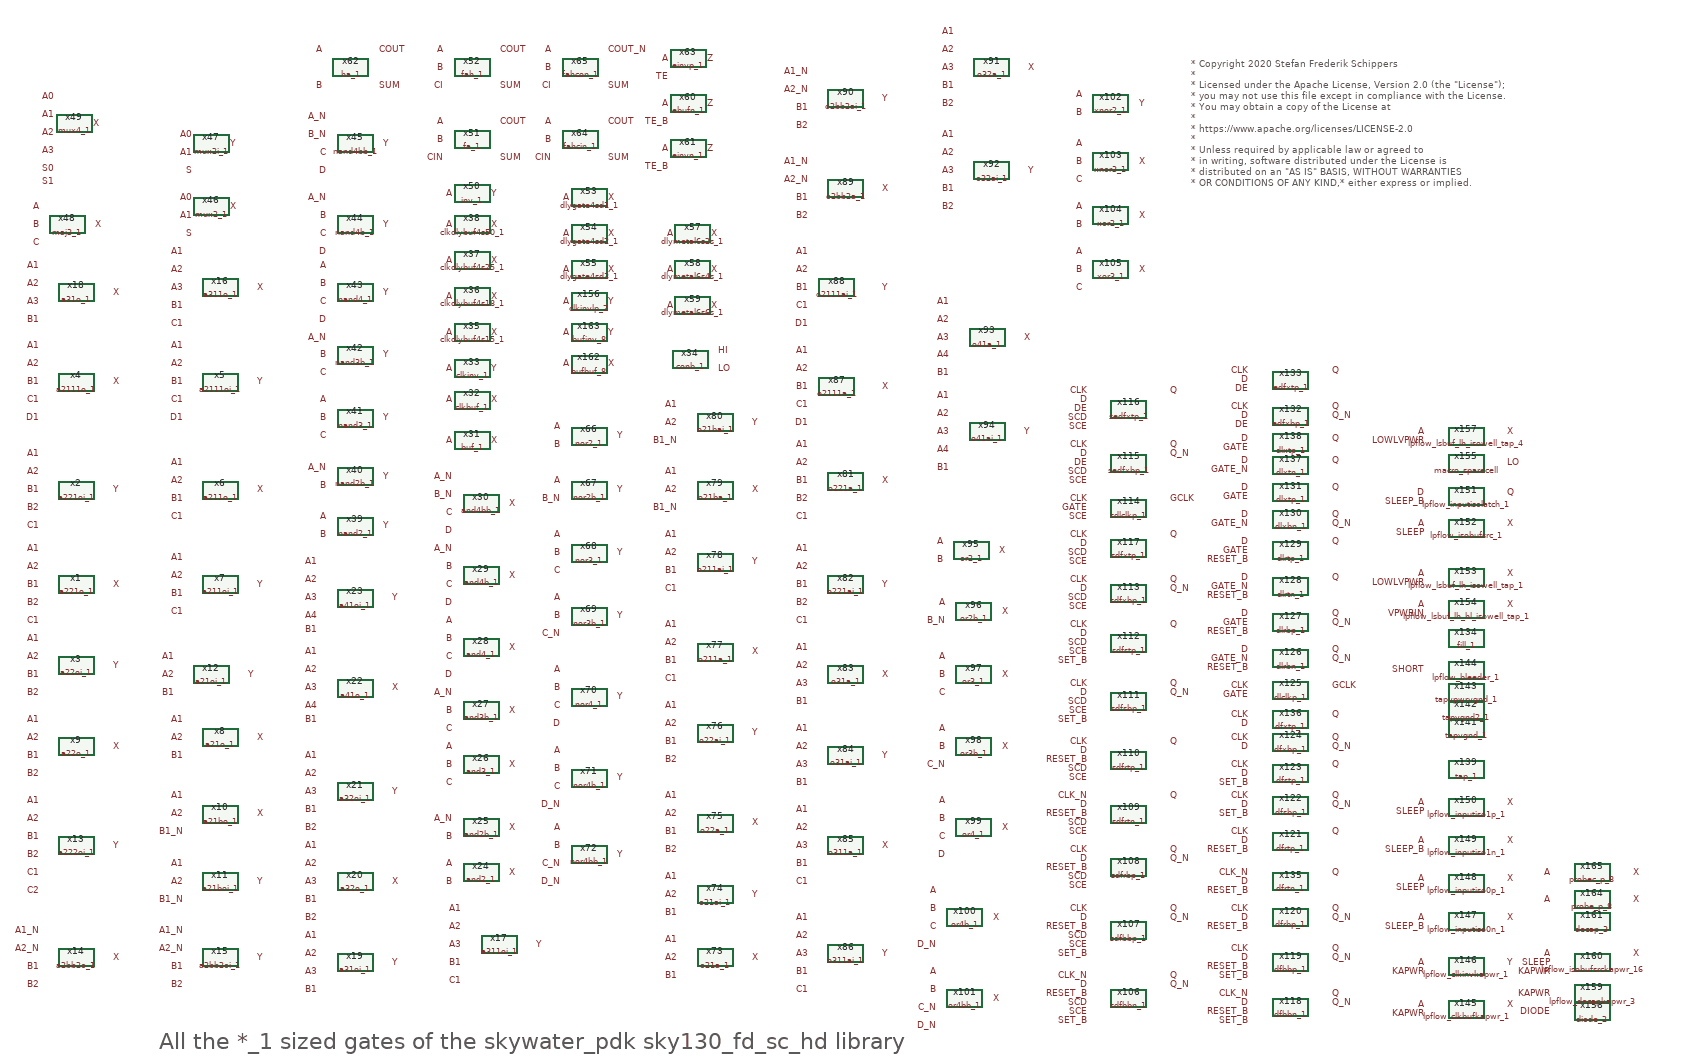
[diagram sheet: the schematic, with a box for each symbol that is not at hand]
v {xschem version=2.9.9 file_version=1.2 }
G {}
K {}
V {}
S {}
E {}
T {All the *_1 sized gates of the skywater_pdk sky130_fd_sc_hd library} 345 -215 0 0 2 2 {layer=1}
T {* Copyright 2020 Stefan Frederik Schippers
* 
* Licensed under the Apache License, Version 2.0 (the "License");
* you may not use this file except in compliance with the License.
* You may obtain a copy of the License at
*
*     https://www.apache.org/licenses/LICENSE-2.0
*
* Unless required by applicable law or agreed to
* in writing, software distributed under the License is
* distributed on an "AS IS" BASIS, WITHOUT WARRANTIES
* OR CONDITIONS OF ANY KIND,* either express or implied.
* See the License for the specific language governing
* permissions and limitations under the License.
} 2640 -2390 0 0 0.6 0.6 {}
C {sky130_stdcells/a221o_1.sym} 160 -1220 0 0 {name=x1 VGND=VGND VNB=VNB VPB=VPB VPWR=VPWR prefix=sky130_fd_sc_hd__ }
C {devices/lab_pin.sym} 80 -1300 0 0 {name=p1 lab=A1}
C {devices/lab_pin.sym} 80 -1260 0 0 {name=p2 lab=A2}
C {devices/lab_pin.sym} 80 -1220 0 0 {name=p3 lab=B1}
C {devices/lab_pin.sym} 80 -1180 0 0 {name=p4 lab=B2}
C {devices/lab_pin.sym} 80 -1140 0 0 {name=p5 lab=C1}
C {devices/lab_pin.sym} 240 -1220 0 1 {name=p6 lab=X}
C {sky130_stdcells/a221oi_1.sym} 160 -1430 0 0 {name=x2 VGND=VGND VNB=VNB VPB=VPB VPWR=VPWR prefix=sky130_fd_sc_hd__ }
C {devices/lab_pin.sym} 80 -1510 0 0 {name=p7 lab=A1}
C {devices/lab_pin.sym} 80 -1470 0 0 {name=p8 lab=A2}
C {devices/lab_pin.sym} 80 -1430 0 0 {name=p9 lab=B1}
C {devices/lab_pin.sym} 80 -1390 0 0 {name=p10 lab=B2}
C {devices/lab_pin.sym} 80 -1350 0 0 {name=p11 lab=C1}
C {sky130_stdcells/a22oi_1.sym} 160 -1040 0 0 {name=x3 VGND=VGND VNB=VNB VPB=VPB VPWR=VPWR prefix=sky130_fd_sc_hd__ }
C {devices/lab_pin.sym} 80 -1100 0 0 {name=p13 lab=A1}
C {devices/lab_pin.sym} 80 -1060 0 0 {name=p14 lab=A2}
C {devices/lab_pin.sym} 80 -1020 0 0 {name=p15 lab=B1}
C {devices/lab_pin.sym} 80 -980 0 0 {name=p16 lab=B2}
C {devices/lab_pin.sym} 240 -1040 0 1 {name=p17 lab=Y}
C {devices/title.sym} 160 -30 0 0 {name=l1 author="Stefan Schippers"}
C {sky130_stdcells/a2111o_1.sym} 160 -1670 0 0 {name=x4 VGND=VGND VNB=VNB VPB=VPB VPWR=VPWR prefix=sky130_fd_sc_hd__ }
C {devices/lab_pin.sym} 80 -1750 0 0 {name=p18 lab=A1}
C {devices/lab_pin.sym} 80 -1710 0 0 {name=p19 lab=A2}
C {devices/lab_pin.sym} 80 -1670 0 0 {name=p20 lab=B1}
C {devices/lab_pin.sym} 80 -1630 0 0 {name=p21 lab=C1}
C {devices/lab_pin.sym} 80 -1590 0 0 {name=p22 lab=D1}
C {devices/lab_pin.sym} 240 -1670 0 1 {name=p23 lab=X}
C {sky130_stdcells/a2111oi_1.sym} 480 -1670 0 0 {name=x5 VGND=VGND VNB=VNB VPB=VPB VPWR=VPWR prefix=sky130_fd_sc_hd__ }
C {devices/lab_pin.sym} 400 -1750 0 0 {name=p24 lab=A1}
C {devices/lab_pin.sym} 400 -1710 0 0 {name=p25 lab=A2}
C {devices/lab_pin.sym} 400 -1670 0 0 {name=p26 lab=B1}
C {devices/lab_pin.sym} 400 -1630 0 0 {name=p27 lab=C1}
C {devices/lab_pin.sym} 400 -1590 0 0 {name=p28 lab=D1}
C {sky130_stdcells/a211o_1.sym} 480 -1430 0 0 {name=x6 VGND=VGND VNB=VNB VPB=VPB VPWR=VPWR prefix=sky130_fd_sc_hd__ }
C {devices/lab_pin.sym} 400 -1490 0 0 {name=p30 lab=A1}
C {devices/lab_pin.sym} 400 -1450 0 0 {name=p31 lab=A2}
C {devices/lab_pin.sym} 400 -1410 0 0 {name=p32 lab=B1}
C {devices/lab_pin.sym} 400 -1370 0 0 {name=p33 lab=C1}
C {devices/lab_pin.sym} 560 -1430 0 1 {name=p34 lab=X}
C {sky130_stdcells/a211oi_1.sym} 480 -1220 0 0 {name=x7 VGND=VGND VNB=VNB VPB=VPB VPWR=VPWR prefix=sky130_fd_sc_hd__ }
C {devices/lab_pin.sym} 400 -1280 0 0 {name=p35 lab=A1}
C {devices/lab_pin.sym} 400 -1240 0 0 {name=p36 lab=A2}
C {devices/lab_pin.sym} 400 -1200 0 0 {name=p37 lab=B1}
C {devices/lab_pin.sym} 400 -1160 0 0 {name=p38 lab=C1}
C {devices/lab_pin.sym} 560 -1220 0 1 {name=p39 lab=Y}
C {devices/lab_pin.sym} 560 -1670 0 1 {name=p29 lab=Y}
C {devices/lab_pin.sym} 240 -1430 0 1 {name=p12 lab=Y}
C {sky130_stdcells/a21o_1.sym} 480 -880 0 0 {name=x8 VGND=VGND VNB=VNB VPB=VPB VPWR=VPWR prefix=sky130_fd_sc_hd__ }
C {devices/lab_pin.sym} 400 -920 0 0 {name=p40 lab=A1}
C {devices/lab_pin.sym} 400 -880 0 0 {name=p41 lab=A2}
C {devices/lab_pin.sym} 400 -840 0 0 {name=p42 lab=B1}
C {devices/lab_pin.sym} 560 -880 0 1 {name=p43 lab=X}
C {sky130_stdcells/a22o_1.sym} 160 -860 0 0 {name=x9 VGND=VGND VNB=VNB VPB=VPB VPWR=VPWR prefix=sky130_fd_sc_hd__ }
C {devices/lab_pin.sym} 80 -920 0 0 {name=p44 lab=A1}
C {devices/lab_pin.sym} 80 -880 0 0 {name=p45 lab=A2}
C {devices/lab_pin.sym} 80 -840 0 0 {name=p46 lab=B1}
C {devices/lab_pin.sym} 80 -800 0 0 {name=p47 lab=B2}
C {devices/lab_pin.sym} 240 -860 0 1 {name=p48 lab=X}
C {sky130_stdcells/a21bo_1.sym} 480 -710 0 0 {name=x10 VGND=VGND VNB=VNB VPB=VPB VPWR=VPWR prefix=sky130_fd_sc_hd__ }
C {devices/lab_pin.sym} 400 -750 0 0 {name=p49 lab=A1}
C {devices/lab_pin.sym} 400 -710 0 0 {name=p50 lab=A2}
C {devices/lab_pin.sym} 400 -670 0 0 {name=p51 lab=B1_N}
C {devices/lab_pin.sym} 560 -710 0 1 {name=p52 lab=X}
C {sky130_stdcells/a21boi_1.sym} 480 -560 0 0 {name=x11 VGND=VGND VNB=VNB VPB=VPB VPWR=VPWR prefix=sky130_fd_sc_hd__ }
C {devices/lab_pin.sym} 400 -600 0 0 {name=p53 lab=A1}
C {devices/lab_pin.sym} 400 -560 0 0 {name=p54 lab=A2}
C {devices/lab_pin.sym} 400 -520 0 0 {name=p55 lab=B1_N}
C {devices/lab_pin.sym} 560 -560 0 1 {name=p56 lab=Y}
C {sky130_stdcells/a21oi_1.sym} 460 -1020 0 0 {name=x12 VGND=VGND VNB=VNB VPB=VPB VPWR=VPWR prefix=sky130_fd_sc_hd__ }
C {devices/lab_pin.sym} 380 -1060 0 0 {name=p57 lab=A1}
C {devices/lab_pin.sym} 380 -1020 0 0 {name=p58 lab=A2}
C {devices/lab_pin.sym} 380 -980 0 0 {name=p59 lab=B1}
C {devices/lab_pin.sym} 540 -1020 0 1 {name=p60 lab=Y}
C {sky130_stdcells/a222oi_1.sym} 160 -640 0 0 {name=x13 VGND=VGND VNB=VNB VPB=VPB VPWR=VPWR prefix=sky130_fd_sc_hd__ }
C {devices/lab_pin.sym} 80 -740 0 0 {name=p61 lab=A1}
C {devices/lab_pin.sym} 80 -700 0 0 {name=p62 lab=A2}
C {devices/lab_pin.sym} 80 -660 0 0 {name=p63 lab=B1}
C {devices/lab_pin.sym} 80 -620 0 0 {name=p64 lab=B2}
C {devices/lab_pin.sym} 80 -580 0 0 {name=p65 lab=C1}
C {devices/lab_pin.sym} 80 -540 0 0 {name=p66 lab=C2}
C {devices/lab_pin.sym} 240 -640 0 1 {name=p67 lab=Y}
C {sky130_stdcells/a2bb2o_1.sym} 160 -390 0 0 {name=x14 VGND=VGND VNB=VNB VPB=VPB VPWR=VPWR prefix=sky130_fd_sc_hd__ }
C {devices/lab_pin.sym} 80 -450 0 0 {name=p68 lab=A1_N}
C {devices/lab_pin.sym} 80 -410 0 0 {name=p69 lab=A2_N}
C {devices/lab_pin.sym} 80 -370 0 0 {name=p70 lab=B1}
C {devices/lab_pin.sym} 80 -330 0 0 {name=p71 lab=B2}
C {devices/lab_pin.sym} 240 -390 0 1 {name=p72 lab=X}
C {sky130_stdcells/a2bb2oi_1.sym} 480 -390 0 0 {name=x15 VGND=VGND VNB=VNB VPB=VPB VPWR=VPWR prefix=sky130_fd_sc_hd__ }
C {devices/lab_pin.sym} 400 -450 0 0 {name=p73 lab=A1_N}
C {devices/lab_pin.sym} 400 -410 0 0 {name=p74 lab=A2_N}
C {devices/lab_pin.sym} 400 -370 0 0 {name=p75 lab=B1}
C {devices/lab_pin.sym} 400 -330 0 0 {name=p76 lab=B2}
C {devices/lab_pin.sym} 560 -390 0 1 {name=p77 lab=Y}
C {sky130_stdcells/a311o_1.sym} 480 -1880 0 0 {name=x16 VGND=VGND VNB=VNB VPB=VPB VPWR=VPWR prefix=sky130_fd_sc_hd__ }
C {devices/lab_pin.sym} 400 -1960 0 0 {name=p78 lab=A1}
C {devices/lab_pin.sym} 400 -1920 0 0 {name=p79 lab=A2}
C {devices/lab_pin.sym} 400 -1880 0 0 {name=p80 lab=A3}
C {devices/lab_pin.sym} 400 -1840 0 0 {name=p81 lab=B1}
C {devices/lab_pin.sym} 400 -1800 0 0 {name=p82 lab=C1}
C {devices/lab_pin.sym} 560 -1880 0 1 {name=p83 lab=X}
C {sky130_stdcells/a311oi_1.sym} 1100 -420 0 0 {name=x17 VGND=VGND VNB=VNB VPB=VPB VPWR=VPWR prefix=sky130_fd_sc_hd__ }
C {devices/lab_pin.sym} 1020 -500 0 0 {name=p84 lab=A1}
C {devices/lab_pin.sym} 1020 -460 0 0 {name=p85 lab=A2}
C {devices/lab_pin.sym} 1020 -420 0 0 {name=p86 lab=A3}
C {devices/lab_pin.sym} 1020 -380 0 0 {name=p87 lab=B1}
C {devices/lab_pin.sym} 1020 -340 0 0 {name=p88 lab=C1}
C {devices/lab_pin.sym} 1180 -420 0 1 {name=p89 lab=Y}
C {sky130_stdcells/a31o_1.sym} 160 -1870 0 0 {name=x18 VGND=VGND VNB=VNB VPB=VPB VPWR=VPWR prefix=sky130_fd_sc_hd__ }
C {devices/lab_pin.sym} 80 -1930 0 0 {name=p90 lab=A1}
C {devices/lab_pin.sym} 80 -1890 0 0 {name=p91 lab=A2}
C {devices/lab_pin.sym} 80 -1850 0 0 {name=p92 lab=A3}
C {devices/lab_pin.sym} 80 -1810 0 0 {name=p93 lab=B1}
C {devices/lab_pin.sym} 240 -1870 0 1 {name=p94 lab=X}
C {sky130_stdcells/a31oi_1.sym} 780 -380 0 0 {name=x19 VGND=VGND VNB=VNB VPB=VPB VPWR=VPWR prefix=sky130_fd_sc_hd__ }
C {devices/lab_pin.sym} 700 -440 0 0 {name=p95 lab=A1}
C {devices/lab_pin.sym} 700 -400 0 0 {name=p96 lab=A2}
C {devices/lab_pin.sym} 700 -360 0 0 {name=p97 lab=A3}
C {devices/lab_pin.sym} 700 -320 0 0 {name=p98 lab=B1}
C {devices/lab_pin.sym} 860 -380 0 1 {name=p99 lab=Y}
C {sky130_stdcells/a32o_1.sym} 780 -560 0 0 {name=x20 VGND=VGND VNB=VNB VPB=VPB VPWR=VPWR prefix=sky130_fd_sc_hd__ }
C {devices/lab_pin.sym} 700 -640 0 0 {name=p100 lab=A1}
C {devices/lab_pin.sym} 700 -600 0 0 {name=p101 lab=A2}
C {devices/lab_pin.sym} 700 -560 0 0 {name=p102 lab=A3}
C {devices/lab_pin.sym} 700 -520 0 0 {name=p103 lab=B1}
C {devices/lab_pin.sym} 700 -480 0 0 {name=p104 lab=B2}
C {devices/lab_pin.sym} 860 -560 0 1 {name=p105 lab=X}
C {sky130_stdcells/a32oi_1.sym} 780 -760 0 0 {name=x21 VGND=VGND VNB=VNB VPB=VPB VPWR=VPWR prefix=sky130_fd_sc_hd__ }
C {devices/lab_pin.sym} 700 -840 0 0 {name=p106 lab=A1}
C {devices/lab_pin.sym} 700 -800 0 0 {name=p107 lab=A2}
C {devices/lab_pin.sym} 700 -760 0 0 {name=p108 lab=A3}
C {devices/lab_pin.sym} 700 -720 0 0 {name=p109 lab=B1}
C {devices/lab_pin.sym} 700 -680 0 0 {name=p110 lab=B2}
C {devices/lab_pin.sym} 860 -760 0 1 {name=p111 lab=Y}
C {sky130_stdcells/a41o_1.sym} 780 -990 0 0 {name=x22 VGND=VGND VNB=VNB VPB=VPB VPWR=VPWR prefix=sky130_fd_sc_hd__ }
C {devices/lab_pin.sym} 700 -1070 0 0 {name=p112 lab=A1}
C {devices/lab_pin.sym} 700 -1030 0 0 {name=p113 lab=A2}
C {devices/lab_pin.sym} 700 -990 0 0 {name=p114 lab=A3}
C {devices/lab_pin.sym} 700 -950 0 0 {name=p115 lab=A4}
C {devices/lab_pin.sym} 700 -920 0 0 {name=p116 lab=B1}
C {devices/lab_pin.sym} 860 -990 0 1 {name=p117 lab=X}
C {sky130_stdcells/a41oi_1.sym} 780 -1190 0 0 {name=x23 VGND=VGND VNB=VNB VPB=VPB VPWR=VPWR prefix=sky130_fd_sc_hd__ }
C {devices/lab_pin.sym} 700 -1270 0 0 {name=p118 lab=A1}
C {devices/lab_pin.sym} 700 -1230 0 0 {name=p119 lab=A2}
C {devices/lab_pin.sym} 700 -1190 0 0 {name=p120 lab=A3}
C {devices/lab_pin.sym} 700 -1150 0 0 {name=p121 lab=A4}
C {devices/lab_pin.sym} 700 -1120 0 0 {name=p122 lab=B1}
C {devices/lab_pin.sym} 860 -1190 0 1 {name=p123 lab=Y}
C {sky130_stdcells/and2_1.sym} 1060 -580 0 0 {name=x24 VGND=VGND VNB=VNB VPB=VPB VPWR=VPWR prefix=sky130_fd_sc_hd__ }
C {devices/lab_pin.sym} 1000 -600 0 0 {name=p124 lab=A}
C {devices/lab_pin.sym} 1000 -560 0 0 {name=p125 lab=B}
C {devices/lab_pin.sym} 1120 -580 0 1 {name=p126 lab=X}
C {sky130_stdcells/and2b_1.sym} 1060 -680 0 0 {name=x25 VGND=VGND VNB=VNB VPB=VPB VPWR=VPWR prefix=sky130_fd_sc_hd__ }
C {devices/lab_pin.sym} 1000 -700 0 0 {name=p127 lab=A_N}
C {devices/lab_pin.sym} 1000 -660 0 0 {name=p128 lab=B}
C {devices/lab_pin.sym} 1120 -680 0 1 {name=p129 lab=X}
C {sky130_stdcells/and3_1.sym} 1060 -820 0 0 {name=x26 VGND=VGND VNB=VNB VPB=VPB VPWR=VPWR prefix=sky130_fd_sc_hd__ }
C {devices/lab_pin.sym} 1000 -860 0 0 {name=p130 lab=A}
C {devices/lab_pin.sym} 1000 -820 0 0 {name=p131 lab=B}
C {devices/lab_pin.sym} 1000 -780 0 0 {name=p132 lab=C}
C {devices/lab_pin.sym} 1120 -820 0 1 {name=p133 lab=X}
C {sky130_stdcells/and3b_1.sym} 1060 -940 0 0 {name=x27 VGND=VGND VNB=VNB VPB=VPB VPWR=VPWR prefix=sky130_fd_sc_hd__ }
C {devices/lab_pin.sym} 1000 -980 0 0 {name=p134 lab=A_N}
C {devices/lab_pin.sym} 1000 -940 0 0 {name=p135 lab=B}
C {devices/lab_pin.sym} 1000 -900 0 0 {name=p136 lab=C}
C {devices/lab_pin.sym} 1120 -940 0 1 {name=p137 lab=X}
C {sky130_stdcells/and4_1.sym} 1060 -1080 0 0 {name=x28 VGND=VGND VNB=VNB VPB=VPB VPWR=VPWR prefix=sky130_fd_sc_hd__ }
C {devices/lab_pin.sym} 1000 -1140 0 0 {name=p138 lab=A}
C {devices/lab_pin.sym} 1000 -1100 0 0 {name=p139 lab=B}
C {devices/lab_pin.sym} 1000 -1060 0 0 {name=p140 lab=C}
C {devices/lab_pin.sym} 1000 -1020 0 0 {name=p141 lab=D}
C {devices/lab_pin.sym} 1120 -1080 0 1 {name=p142 lab=X}
C {sky130_stdcells/and4b_1.sym} 1060 -1240 0 0 {name=x29 VGND=VGND VNB=VNB VPB=VPB VPWR=VPWR prefix=sky130_fd_sc_hd__ }
C {devices/lab_pin.sym} 1000 -1300 0 0 {name=p143 lab=A_N}
C {devices/lab_pin.sym} 1000 -1260 0 0 {name=p144 lab=B}
C {devices/lab_pin.sym} 1000 -1220 0 0 {name=p145 lab=C}
C {devices/lab_pin.sym} 1000 -1180 0 0 {name=p146 lab=D}
C {devices/lab_pin.sym} 1120 -1240 0 1 {name=p147 lab=X}
C {sky130_stdcells/and4bb_1.sym} 1060 -1400 0 0 {name=x30 VGND=VGND VNB=VNB VPB=VPB VPWR=VPWR prefix=sky130_fd_sc_hd__ }
C {devices/lab_pin.sym} 1000 -1460 0 0 {name=p148 lab=A_N}
C {devices/lab_pin.sym} 1000 -1420 0 0 {name=p149 lab=B_N}
C {devices/lab_pin.sym} 1000 -1380 0 0 {name=p150 lab=C}
C {devices/lab_pin.sym} 1000 -1340 0 0 {name=p151 lab=D}
C {devices/lab_pin.sym} 1120 -1400 0 1 {name=p152 lab=X}
C {sky130_stdcells/buf_1.sym} 1040 -1540 0 0 {name=x31 VGND=VGND VNB=VNB VPB=VPB VPWR=VPWR prefix=sky130_fd_sc_hd__ }
C {devices/lab_pin.sym} 1000 -1540 0 0 {name=p153 lab=A}
C {devices/lab_pin.sym} 1080 -1540 0 1 {name=p154 lab=X}
C {sky130_stdcells/clkbuf_1.sym} 1040 -1630 0 0 {name=x32 VGND=VGND VNB=VNB VPB=VPB VPWR=VPWR prefix=sky130_fd_sc_hd__ }
C {devices/lab_pin.sym} 1000 -1630 0 0 {name=p155 lab=A}
C {devices/lab_pin.sym} 1080 -1630 0 1 {name=p156 lab=X}
C {sky130_stdcells/clkinv_1.sym} 1040 -1700 0 0 {name=x33 VGND=VGND VNB=VNB VPB=VPB VPWR=VPWR prefix=sky130_fd_sc_hd__ }
C {devices/lab_pin.sym} 1000 -1700 0 0 {name=p157 lab=A}
C {devices/lab_pin.sym} 1080 -1700 0 1 {name=p158 lab=Y}
C {sky130_stdcells/conb_1.sym} 1525 -1720 0 0 {name=x34 VGND=VGND VNB=VNB VPB=VPB VPWR=VPWR prefix=sky130_fd_sc_hd__ }
C {devices/lab_pin.sym} 1585 -1740 0 1 {name=p159 lab=HI}
C {devices/lab_pin.sym} 1585 -1700 0 1 {name=p160 lab=LO}
C {sky130_stdcells/clkdlybuf4s15_1.sym} 1040 -1780 0 0 {name=x35 VGND=VGND VNB=VNB VPB=VPB VPWR=VPWR prefix=sky130_fd_sc_hd__ }
C {devices/lab_pin.sym} 1000 -1780 0 0 {name=p161 lab=A}
C {devices/lab_pin.sym} 1080 -1780 0 1 {name=p162 lab=X}
C {sky130_stdcells/clkdlybuf4s18_1.sym} 1040 -1860 0 0 {name=x36 VGND=VGND VNB=VNB VPB=VPB VPWR=VPWR prefix=sky130_fd_sc_hd__ }
C {devices/lab_pin.sym} 1000 -1860 0 0 {name=p163 lab=A}
C {devices/lab_pin.sym} 1080 -1860 0 1 {name=p164 lab=X}
C {sky130_stdcells/clkdlybuf4s25_1.sym} 1040 -1940 0 0 {name=x37 VGND=VGND VNB=VNB VPB=VPB VPWR=VPWR prefix=sky130_fd_sc_hd__ }
C {devices/lab_pin.sym} 1000 -1940 0 0 {name=p165 lab=A}
C {devices/lab_pin.sym} 1080 -1940 0 1 {name=p166 lab=X}
C {sky130_stdcells/clkdlybuf4s50_1.sym} 1040 -2020 0 0 {name=x38 VGND=VGND VNB=VNB VPB=VPB VPWR=VPWR prefix=sky130_fd_sc_hd__ }
C {devices/lab_pin.sym} 1000 -2020 0 0 {name=p167 lab=A}
C {devices/lab_pin.sym} 1080 -2020 0 1 {name=p168 lab=X}
C {sky130_stdcells/nand2_1.sym} 780 -1350 0 0 {name=x39 VGND=VGND VNB=VNB VPB=VPB VPWR=VPWR prefix=sky130_fd_sc_hd__ }
C {devices/lab_pin.sym} 720 -1370 0 0 {name=p169 lab=A}
C {devices/lab_pin.sym} 720 -1330 0 0 {name=p170 lab=B}
C {devices/lab_pin.sym} 840 -1350 0 1 {name=p171 lab=Y}
C {sky130_stdcells/nand2b_1.sym} 780 -1460 0 0 {name=x40 VGND=VGND VNB=VNB VPB=VPB VPWR=VPWR prefix=sky130_fd_sc_hd__ }
C {devices/lab_pin.sym} 720 -1480 0 0 {name=p172 lab=A_N}
C {devices/lab_pin.sym} 720 -1440 0 0 {name=p173 lab=B}
C {devices/lab_pin.sym} 840 -1460 0 1 {name=p174 lab=Y}
C {sky130_stdcells/nand3_1.sym} 780 -1590 0 0 {name=x41 VGND=VGND VNB=VNB VPB=VPB VPWR=VPWR prefix=sky130_fd_sc_hd__ }
C {devices/lab_pin.sym} 720 -1630 0 0 {name=p175 lab=A}
C {devices/lab_pin.sym} 720 -1590 0 0 {name=p176 lab=B}
C {devices/lab_pin.sym} 720 -1550 0 0 {name=p177 lab=C}
C {devices/lab_pin.sym} 840 -1590 0 1 {name=p178 lab=Y}
C {sky130_stdcells/nand3b_1.sym} 780 -1730 0 0 {name=x42 VGND=VGND VNB=VNB VPB=VPB VPWR=VPWR prefix=sky130_fd_sc_hd__ }
C {devices/lab_pin.sym} 720 -1730 0 0 {name=p180 lab=B}
C {devices/lab_pin.sym} 720 -1690 0 0 {name=p181 lab=C}
C {devices/lab_pin.sym} 840 -1730 0 1 {name=p182 lab=Y}
C {sky130_stdcells/nand4_1.sym} 780 -1870 0 0 {name=x43 VGND=VGND VNB=VNB VPB=VPB VPWR=VPWR prefix=sky130_fd_sc_hd__ }
C {devices/lab_pin.sym} 720 -1930 0 0 {name=p183 lab=A}
C {devices/lab_pin.sym} 720 -1890 0 0 {name=p184 lab=B}
C {devices/lab_pin.sym} 720 -1850 0 0 {name=p185 lab=C}
C {devices/lab_pin.sym} 720 -1810 0 0 {name=p186 lab=D}
C {devices/lab_pin.sym} 840 -1870 0 1 {name=p187 lab=Y}
C {sky130_stdcells/nand4b_1.sym} 780 -2020 0 0 {name=x44 VGND=VGND VNB=VNB VPB=VPB VPWR=VPWR prefix=sky130_fd_sc_hd__ }
C {devices/lab_pin.sym} 720 -2080 0 0 {name=p188 lab=A_N}
C {devices/lab_pin.sym} 720 -2040 0 0 {name=p189 lab=B}
C {devices/lab_pin.sym} 720 -2000 0 0 {name=p190 lab=C}
C {devices/lab_pin.sym} 720 -1960 0 0 {name=p191 lab=D}
C {devices/lab_pin.sym} 840 -2020 0 1 {name=p192 lab=Y}
C {sky130_stdcells/nand4bb_1.sym} 780 -2200 0 0 {name=x45 VGND=VGND VNB=VNB VPB=VPB VPWR=VPWR prefix=sky130_fd_sc_hd__ }
C {devices/lab_pin.sym} 720 -2260 0 0 {name=p193 lab=A_N}
C {devices/lab_pin.sym} 720 -2220 0 0 {name=p194 lab=B_N}
C {devices/lab_pin.sym} 720 -2180 0 0 {name=p195 lab=C}
C {devices/lab_pin.sym} 720 -2140 0 0 {name=p196 lab=D}
C {devices/lab_pin.sym} 840 -2200 0 1 {name=p197 lab=Y}
C {sky130_stdcells/mux2_1.sym} 460 -2060 0 0 {name=x46 VGND=VGND VNB=VNB VPB=VPB VPWR=VPWR prefix=sky130_fd_sc_hd__ }
C {devices/lab_pin.sym} 420 -2080 0 0 {name=p198 lab=A0}
C {devices/lab_pin.sym} 420 -2040 0 0 {name=p199 lab=A1}
C {devices/lab_pin.sym} 420 -2000 0 0 {name=p200 lab=S}
C {devices/lab_pin.sym} 500 -2060 0 1 {name=p201 lab=X}
C {sky130_stdcells/mux2i_1.sym} 460 -2200 0 0 {name=x47 VGND=VGND VNB=VNB VPB=VPB VPWR=VPWR prefix=sky130_fd_sc_hd__ }
C {devices/lab_pin.sym} 420 -2220 0 0 {name=p202 lab=A0}
C {devices/lab_pin.sym} 420 -2180 0 0 {name=p203 lab=A1}
C {devices/lab_pin.sym} 420 -2140 0 0 {name=p204 lab=S}
C {devices/lab_pin.sym} 500 -2200 0 1 {name=p205 lab=Y}
C {sky130_stdcells/maj3_1.sym} 140 -2020 0 0 {name=x48 VGND=VGND VNB=VNB VPB=VPB VPWR=VPWR prefix=sky130_fd_sc_hd__ }
C {devices/lab_pin.sym} 80 -2060 0 0 {name=p206 lab=A}
C {devices/lab_pin.sym} 80 -2020 0 0 {name=p207 lab=B}
C {devices/lab_pin.sym} 80 -1980 0 0 {name=p208 lab=C}
C {devices/lab_pin.sym} 200 -2020 0 1 {name=p209 lab=X}
C {sky130_stdcells/mux4_1.sym} 155 -2245 0 0 {name=x49 VGND=VGND VNB=VNB VPB=VPB VPWR=VPWR prefix=sky130_fd_sc_hd__ }
C {devices/lab_pin.sym} 115 -2305 0 0 {name=p210 lab=A0}
C {devices/lab_pin.sym} 115 -2265 0 0 {name=p211 lab=A1}
C {devices/lab_pin.sym} 115 -2225 0 0 {name=p212 lab=A2}
C {devices/lab_pin.sym} 115 -2185 0 0 {name=p213 lab=A3}
C {devices/lab_pin.sym} 115 -2145 0 0 {name=p214 lab=S0}
C {devices/lab_pin.sym} 115 -2115 0 0 {name=p215 lab=S1}
C {devices/lab_pin.sym} 195 -2245 0 1 {name=p216 lab=X}
C {sky130_stdcells/inv_1.sym} 1040 -2090 0 0 {name=x50 VGND=VGND VNB=VNB VPB=VPB VPWR=VPWR prefix=sky130_fd_sc_hd__ }
C {devices/lab_pin.sym} 1000 -2090 0 0 {name=p217 lab=A}
C {devices/lab_pin.sym} 1080 -2090 0 1 {name=p218 lab=Y}
C {sky130_stdcells/fa_1.sym} 1040 -2210 0 0 {name=x51 VGND=VGND VNB=VNB VPB=VPB VPWR=VPWR prefix=sky130_fd_sc_hd__ }
C {devices/lab_pin.sym} 980 -2250 0 0 {name=p219 lab=A}
C {devices/lab_pin.sym} 980 -2210 0 0 {name=p220 lab=B}
C {devices/lab_pin.sym} 980 -2170 0 0 {name=p221 lab=CIN}
C {devices/lab_pin.sym} 1100 -2250 0 1 {name=p222 lab=COUT}
C {devices/lab_pin.sym} 1100 -2170 0 1 {name=p223 lab=SUM}
C {sky130_stdcells/fah_1.sym} 1040 -2370 0 0 {name=x52 VGND=VGND VNB=VNB VPB=VPB VPWR=VPWR prefix=sky130_fd_sc_hd__ }
C {devices/lab_pin.sym} 980 -2410 0 0 {name=p224 lab=A}
C {devices/lab_pin.sym} 980 -2370 0 0 {name=p225 lab=B}
C {devices/lab_pin.sym} 980 -2330 0 0 {name=p226 lab=CI}
C {devices/lab_pin.sym} 1100 -2410 0 1 {name=p227 lab=COUT}
C {devices/lab_pin.sym} 1100 -2330 0 1 {name=p228 lab=SUM}
C {sky130_stdcells/dlygate4sd1_1.sym} 1300 -2080 0 0 {name=x53 VGND=VGND VNB=VNB VPB=VPB VPWR=VPWR prefix=sky130_fd_sc_hd__ }
C {sky130_stdcells/dlygate4sd2_1.sym} 1300 -2000 0 0 {name=x54 VGND=VGND VNB=VNB VPB=VPB VPWR=VPWR prefix=sky130_fd_sc_hd__ }
C {sky130_stdcells/dlygate4sd3_1.sym} 1300 -1920 0 0 {name=x55 VGND=VGND VNB=VNB VPB=VPB VPWR=VPWR prefix=sky130_fd_sc_hd__ }
C {devices/lab_pin.sym} 1260 -2080 0 0 {name=p229 lab=A}
C {devices/lab_pin.sym} 1340 -2080 0 1 {name=p230 lab=X}
C {devices/lab_pin.sym} 1260 -2000 0 0 {name=p231 lab=A}
C {devices/lab_pin.sym} 1340 -2000 0 1 {name=p232 lab=X}
C {devices/lab_pin.sym} 1260 -1920 0 0 {name=p233 lab=A}
C {devices/lab_pin.sym} 1340 -1920 0 1 {name=p234 lab=X}
C {sky130_stdcells/dlymetal6s2s_1.sym} 1530 -2000 0 0 {name=x57 VGND=VGND VNB=VNB VPB=VPB VPWR=VPWR prefix=sky130_fd_sc_hd__ }
C {sky130_stdcells/dlymetal6s4s_1.sym} 1530 -1920 0 0 {name=x58 VGND=VGND VNB=VNB VPB=VPB VPWR=VPWR prefix=sky130_fd_sc_hd__ }
C {sky130_stdcells/dlymetal6s6s_1.sym} 1530 -1840 0 0 {name=x59 VGND=VGND VNB=VNB VPB=VPB VPWR=VPWR prefix=sky130_fd_sc_hd__ }
C {devices/lab_pin.sym} 1490 -2000 0 0 {name=p237 lab=A}
C {devices/lab_pin.sym} 1570 -2000 0 1 {name=p238 lab=X}
C {devices/lab_pin.sym} 1490 -1920 0 0 {name=p239 lab=A}
C {devices/lab_pin.sym} 1570 -1920 0 1 {name=p240 lab=X}
C {devices/lab_pin.sym} 1490 -1840 0 0 {name=p241 lab=A}
C {devices/lab_pin.sym} 1570 -1840 0 1 {name=p242 lab=X}
C {sky130_stdcells/ebufn_1.sym} 1520 -2290 0 0 {name=x60 VGND=VGND VNB=VNB VPB=VPB VPWR=VPWR prefix=sky130_fd_sc_hd__ }
C {devices/lab_pin.sym} 1480 -2290 0 0 {name=p243 lab=A}
C {devices/lab_pin.sym} 1480 -2250 0 0 {name=p244 lab=TE_B}
C {devices/lab_pin.sym} 1560 -2290 0 1 {name=p245 lab=Z}
C {sky130_stdcells/einvn_1.sym} 1520 -2190 0 0 {name=x61 VGND=VGND VNB=VNB VPB=VPB VPWR=VPWR prefix=sky130_fd_sc_hd__ }
C {devices/lab_pin.sym} 1480 -2190 0 0 {name=p246 lab=A}
C {devices/lab_pin.sym} 1480 -2150 0 0 {name=p247 lab=TE_B}
C {devices/lab_pin.sym} 1560 -2190 0 1 {name=p248 lab=Z}
C {sky130_stdcells/ha_1.sym} 770 -2370 0 0 {name=x62 VGND=VGND VNB=VNB VPB=VPB VPWR=VPWR prefix=sky130_fd_sc_hd__ }
C {devices/lab_pin.sym} 710 -2410 0 0 {name=p249 lab=A}
C {devices/lab_pin.sym} 710 -2330 0 0 {name=p250 lab=B}
C {devices/lab_pin.sym} 830 -2410 0 1 {name=p251 lab=COUT}
C {devices/lab_pin.sym} 830 -2330 0 1 {name=p252 lab=SUM}
C {sky130_stdcells/einvp_1.sym} 1520 -2390 0 0 {name=x63 VGND=VGND VNB=VNB VPB=VPB VPWR=VPWR prefix=sky130_fd_sc_hd__ }
C {devices/lab_pin.sym} 1480 -2390 0 0 {name=p253 lab=A}
C {devices/lab_pin.sym} 1480 -2350 0 0 {name=p254 lab=TE}
C {devices/lab_pin.sym} 1560 -2390 0 1 {name=p255 lab=Z}
C {sky130_stdcells/fahcin_1.sym} 1280 -2210 0 0 {name=x64 VGND=VGND VNB=VNB VPB=VPB VPWR=VPWR prefix=sky130_fd_sc_hd__ }
C {devices/lab_pin.sym} 1220 -2250 0 0 {name=p256 lab=A}
C {devices/lab_pin.sym} 1220 -2210 0 0 {name=p257 lab=B}
C {devices/lab_pin.sym} 1220 -2170 0 0 {name=p258 lab=CIN}
C {devices/lab_pin.sym} 1340 -2250 0 1 {name=p259 lab=COUT}
C {devices/lab_pin.sym} 1340 -2170 0 1 {name=p260 lab=SUM}
C {sky130_stdcells/fahcon_1.sym} 1280 -2370 0 0 {name=x65 VGND=VGND VNB=VNB VPB=VPB VPWR=VPWR prefix=sky130_fd_sc_hd__ }
C {devices/lab_pin.sym} 1220 -2410 0 0 {name=p261 lab=A}
C {devices/lab_pin.sym} 1220 -2370 0 0 {name=p262 lab=B}
C {devices/lab_pin.sym} 1220 -2330 0 0 {name=p263 lab=CI}
C {devices/lab_pin.sym} 1340 -2410 0 1 {name=p264 lab=COUT_N}
C {devices/lab_pin.sym} 1340 -2330 0 1 {name=p265 lab=SUM}
C {sky130_stdcells/nor2_1.sym} 1300 -1550 0 0 {name=x66 VGND=VGND VNB=VNB VPB=VPB VPWR=VPWR prefix=sky130_fd_sc_hd__ }
C {devices/lab_pin.sym} 1240 -1570 0 0 {name=p266 lab=A}
C {devices/lab_pin.sym} 1240 -1530 0 0 {name=p267 lab=B}
C {devices/lab_pin.sym} 1360 -1550 0 1 {name=p268 lab=Y}
C {sky130_stdcells/nor2b_1.sym} 1300 -1430 0 0 {name=x67 VGND=VGND VNB=VNB VPB=VPB VPWR=VPWR prefix=sky130_fd_sc_hd__ }
C {devices/lab_pin.sym} 1240 -1450 0 0 {name=p269 lab=A}
C {devices/lab_pin.sym} 1240 -1410 0 0 {name=p270 lab=B_N}
C {devices/lab_pin.sym} 1360 -1430 0 1 {name=p271 lab=Y}
C {sky130_stdcells/nor3_1.sym} 1300 -1290 0 0 {name=x68 VGND=VGND VNB=VNB VPB=VPB VPWR=VPWR prefix=sky130_fd_sc_hd__ }
C {devices/lab_pin.sym} 1240 -1330 0 0 {name=p272 lab=A}
C {devices/lab_pin.sym} 1240 -1290 0 0 {name=p273 lab=B}
C {devices/lab_pin.sym} 1240 -1250 0 0 {name=p274 lab=C}
C {devices/lab_pin.sym} 1360 -1290 0 1 {name=p275 lab=Y}
C {sky130_stdcells/nor3b_1.sym} 1300 -1150 0 0 {name=x69 VGND=VGND VNB=VNB VPB=VPB VPWR=VPWR prefix=sky130_fd_sc_hd__ }
C {devices/lab_pin.sym} 1240 -1190 0 0 {name=p276 lab=A}
C {devices/lab_pin.sym} 1240 -1150 0 0 {name=p277 lab=B}
C {devices/lab_pin.sym} 1240 -1110 0 0 {name=p278 lab=C_N}
C {devices/lab_pin.sym} 1360 -1150 0 1 {name=p279 lab=Y}
C {sky130_stdcells/nor4_1.sym} 1300 -970 0 0 {name=x70 VGND=VGND VNB=VNB VPB=VPB VPWR=VPWR prefix=sky130_fd_sc_hd__ }
C {devices/lab_pin.sym} 1240 -1030 0 0 {name=p280 lab=A}
C {devices/lab_pin.sym} 1240 -990 0 0 {name=p281 lab=B}
C {devices/lab_pin.sym} 1240 -950 0 0 {name=p282 lab=C}
C {devices/lab_pin.sym} 1240 -910 0 0 {name=p283 lab=D}
C {devices/lab_pin.sym} 1360 -970 0 1 {name=p284 lab=Y}
C {sky130_stdcells/nor4b_1.sym} 1300 -790 0 0 {name=x71 VGND=VGND VNB=VNB VPB=VPB VPWR=VPWR prefix=sky130_fd_sc_hd__ }
C {devices/lab_pin.sym} 1240 -850 0 0 {name=p285 lab=A}
C {devices/lab_pin.sym} 1240 -810 0 0 {name=p286 lab=B}
C {devices/lab_pin.sym} 1240 -770 0 0 {name=p287 lab=C}
C {devices/lab_pin.sym} 1240 -730 0 0 {name=p288 lab=D_N}
C {devices/lab_pin.sym} 1360 -790 0 1 {name=p289 lab=Y}
C {sky130_stdcells/nor4bb_1.sym} 1300 -620 0 0 {name=x72 VGND=VGND VNB=VNB VPB=VPB VPWR=VPWR prefix=sky130_fd_sc_hd__ }
C {devices/lab_pin.sym} 1240 -680 0 0 {name=p290 lab=A}
C {devices/lab_pin.sym} 1240 -640 0 0 {name=p291 lab=B}
C {devices/lab_pin.sym} 1240 -600 0 0 {name=p292 lab=C_N}
C {devices/lab_pin.sym} 1240 -560 0 0 {name=p293 lab=D_N}
C {devices/lab_pin.sym} 1360 -620 0 1 {name=p294 lab=Y}
C {sky130_stdcells/o21a_1.sym} 1580 -390 0 0 {name=x73 VGND=VGND VNB=VNB VPB=VPB VPWR=VPWR prefix=sky130_fd_sc_hd__ }
C {devices/lab_pin.sym} 1500 -430 0 0 {name=p295 lab=A1}
C {devices/lab_pin.sym} 1500 -390 0 0 {name=p296 lab=A2}
C {devices/lab_pin.sym} 1500 -350 0 0 {name=p297 lab=B1}
C {devices/lab_pin.sym} 1660 -390 0 1 {name=p298 lab=X}
C {sky130_stdcells/o21ai_1.sym} 1580 -530 0 0 {name=x74 VGND=VGND VNB=VNB VPB=VPB VPWR=VPWR prefix=sky130_fd_sc_hd__ }
C {devices/lab_pin.sym} 1500 -570 0 0 {name=p299 lab=A1}
C {devices/lab_pin.sym} 1500 -530 0 0 {name=p300 lab=A2}
C {devices/lab_pin.sym} 1500 -490 0 0 {name=p301 lab=B1}
C {devices/lab_pin.sym} 1660 -530 0 1 {name=p302 lab=Y}
C {sky130_stdcells/o22a_1.sym} 1580 -690 0 0 {name=x75 VGND=VGND VNB=VNB VPB=VPB VPWR=VPWR prefix=sky130_fd_sc_hd__ }
C {devices/lab_pin.sym} 1500 -750 0 0 {name=p303 lab=A1}
C {devices/lab_pin.sym} 1500 -710 0 0 {name=p304 lab=A2}
C {devices/lab_pin.sym} 1500 -670 0 0 {name=p305 lab=B1}
C {devices/lab_pin.sym} 1500 -630 0 0 {name=p306 lab=B2}
C {devices/lab_pin.sym} 1660 -690 0 1 {name=p307 lab=X}
C {sky130_stdcells/o22ai_1.sym} 1580 -890 0 0 {name=x76 VGND=VGND VNB=VNB VPB=VPB VPWR=VPWR prefix=sky130_fd_sc_hd__ }
C {devices/lab_pin.sym} 1500 -950 0 0 {name=p308 lab=A1}
C {devices/lab_pin.sym} 1500 -910 0 0 {name=p309 lab=A2}
C {devices/lab_pin.sym} 1500 -870 0 0 {name=p310 lab=B1}
C {devices/lab_pin.sym} 1500 -830 0 0 {name=p311 lab=B2}
C {devices/lab_pin.sym} 1660 -890 0 1 {name=p312 lab=Y}
C {sky130_stdcells/o211a_1.sym} 1580 -1070 0 0 {name=x77 VGND=VGND VNB=VNB VPB=VPB VPWR=VPWR prefix=sky130_fd_sc_hd__ }
C {devices/lab_pin.sym} 1500 -1130 0 0 {name=p313 lab=A1}
C {devices/lab_pin.sym} 1500 -1090 0 0 {name=p314 lab=A2}
C {devices/lab_pin.sym} 1500 -1050 0 0 {name=p315 lab=B1}
C {devices/lab_pin.sym} 1500 -1010 0 0 {name=p316 lab=C1}
C {devices/lab_pin.sym} 1660 -1070 0 1 {name=p317 lab=X}
C {sky130_stdcells/o211ai_1.sym} 1580 -1270 0 0 {name=x78 VGND=VGND VNB=VNB VPB=VPB VPWR=VPWR prefix=sky130_fd_sc_hd__ }
C {devices/lab_pin.sym} 1500 -1330 0 0 {name=p318 lab=A1}
C {devices/lab_pin.sym} 1500 -1290 0 0 {name=p319 lab=A2}
C {devices/lab_pin.sym} 1500 -1250 0 0 {name=p320 lab=B1}
C {devices/lab_pin.sym} 1500 -1210 0 0 {name=p321 lab=C1}
C {devices/lab_pin.sym} 1660 -1270 0 1 {name=p322 lab=Y}
C {sky130_stdcells/o21ba_1.sym} 1580 -1430 0 0 {name=x79 VGND=VGND VNB=VNB VPB=VPB VPWR=VPWR prefix=sky130_fd_sc_hd__ }
C {devices/lab_pin.sym} 1500 -1470 0 0 {name=p323 lab=A1}
C {devices/lab_pin.sym} 1500 -1430 0 0 {name=p324 lab=A2}
C {devices/lab_pin.sym} 1500 -1390 0 0 {name=p325 lab=B1_N}
C {devices/lab_pin.sym} 1660 -1430 0 1 {name=p326 lab=X}
C {sky130_stdcells/o21bai_1.sym} 1580 -1580 0 0 {name=x80 VGND=VGND VNB=VNB VPB=VPB VPWR=VPWR prefix=sky130_fd_sc_hd__ }
C {devices/lab_pin.sym} 1500 -1620 0 0 {name=p327 lab=A1}
C {devices/lab_pin.sym} 1500 -1580 0 0 {name=p328 lab=A2}
C {devices/lab_pin.sym} 1500 -1540 0 0 {name=p329 lab=B1_N}
C {devices/lab_pin.sym} 1660 -1580 0 1 {name=p330 lab=Y}
C {sky130_stdcells/o221a_1.sym} 1870 -1450 0 0 {name=x81 VGND=VGND VNB=VNB VPB=VPB VPWR=VPWR prefix=sky130_fd_sc_hd__ }
C {devices/lab_pin.sym} 1790 -1530 0 0 {name=p331 lab=A1}
C {devices/lab_pin.sym} 1790 -1490 0 0 {name=p332 lab=A2}
C {devices/lab_pin.sym} 1790 -1450 0 0 {name=p333 lab=B1}
C {devices/lab_pin.sym} 1790 -1410 0 0 {name=p334 lab=B2}
C {devices/lab_pin.sym} 1790 -1370 0 0 {name=p335 lab=C1}
C {devices/lab_pin.sym} 1950 -1450 0 1 {name=p336 lab=X}
C {sky130_stdcells/o221ai_1.sym} 1870 -1220 0 0 {name=x82 VGND=VGND VNB=VNB VPB=VPB VPWR=VPWR prefix=sky130_fd_sc_hd__ }
C {devices/lab_pin.sym} 1790 -1300 0 0 {name=p337 lab=A1}
C {devices/lab_pin.sym} 1790 -1260 0 0 {name=p338 lab=A2}
C {devices/lab_pin.sym} 1790 -1220 0 0 {name=p339 lab=B1}
C {devices/lab_pin.sym} 1790 -1180 0 0 {name=p340 lab=B2}
C {devices/lab_pin.sym} 1790 -1140 0 0 {name=p341 lab=C1}
C {devices/lab_pin.sym} 1950 -1220 0 1 {name=p342 lab=Y}
C {sky130_stdcells/o31a_1.sym} 1870 -1020 0 0 {name=x83 VGND=VGND VNB=VNB VPB=VPB VPWR=VPWR prefix=sky130_fd_sc_hd__ }
C {devices/lab_pin.sym} 1790 -1080 0 0 {name=p343 lab=A1}
C {devices/lab_pin.sym} 1790 -1040 0 0 {name=p344 lab=A2}
C {devices/lab_pin.sym} 1790 -1000 0 0 {name=p345 lab=A3}
C {devices/lab_pin.sym} 1790 -960 0 0 {name=p346 lab=B1}
C {devices/lab_pin.sym} 1950 -1020 0 1 {name=p347 lab=X}
C {sky130_stdcells/o31ai_1.sym} 1870 -840 0 0 {name=x84 VGND=VGND VNB=VNB VPB=VPB VPWR=VPWR prefix=sky130_fd_sc_hd__ }
C {devices/lab_pin.sym} 1790 -900 0 0 {name=p348 lab=A1}
C {devices/lab_pin.sym} 1790 -860 0 0 {name=p349 lab=A2}
C {devices/lab_pin.sym} 1790 -820 0 0 {name=p350 lab=A3}
C {devices/lab_pin.sym} 1790 -780 0 0 {name=p351 lab=B1}
C {devices/lab_pin.sym} 1950 -840 0 1 {name=p352 lab=Y}
C {sky130_stdcells/o311a_1.sym} 1870 -640 0 0 {name=x85 VGND=VGND VNB=VNB VPB=VPB VPWR=VPWR prefix=sky130_fd_sc_hd__ }
C {devices/lab_pin.sym} 1790 -720 0 0 {name=p353 lab=A1}
C {devices/lab_pin.sym} 1790 -680 0 0 {name=p354 lab=A2}
C {devices/lab_pin.sym} 1790 -640 0 0 {name=p355 lab=A3}
C {devices/lab_pin.sym} 1790 -600 0 0 {name=p356 lab=B1}
C {devices/lab_pin.sym} 1790 -560 0 0 {name=p357 lab=C1}
C {devices/lab_pin.sym} 1950 -640 0 1 {name=p358 lab=X}
C {sky130_stdcells/o311ai_1.sym} 1870 -400 0 0 {name=x86 VGND=VGND VNB=VNB VPB=VPB VPWR=VPWR prefix=sky130_fd_sc_hd__ }
C {devices/lab_pin.sym} 1790 -480 0 0 {name=p359 lab=A1}
C {devices/lab_pin.sym} 1790 -440 0 0 {name=p360 lab=A2}
C {devices/lab_pin.sym} 1790 -400 0 0 {name=p361 lab=A3}
C {devices/lab_pin.sym} 1790 -360 0 0 {name=p362 lab=B1}
C {devices/lab_pin.sym} 1790 -320 0 0 {name=p363 lab=C1}
C {devices/lab_pin.sym} 1950 -400 0 1 {name=p364 lab=Y}
C {sky130_stdcells/o2111a_1.sym} 1850 -1660 0 0 {name=x87 VGND=VGND VNB=VNB VPB=VPB VPWR=VPWR prefix=sky130_fd_sc_hd__ }
C {devices/lab_pin.sym} 1790 -1660 0 0 {name=p367 lab=B1}
C {devices/lab_pin.sym} 1790 -1620 0 0 {name=p368 lab=C1}
C {devices/lab_pin.sym} 1790 -1580 0 0 {name=p369 lab=D1}
C {devices/lab_pin.sym} 1950 -1660 0 1 {name=p370 lab=X}
C {devices/lab_pin.sym} 1790 -1740 0 0 {name=p365 lab=A1}
C {devices/lab_pin.sym} 1790 -1700 0 0 {name=p366 lab=A2}
C {sky130_stdcells/o2111ai_1.sym} 1850 -1880 0 0 {name=x88 VGND=VGND VNB=VNB VPB=VPB VPWR=VPWR prefix=sky130_fd_sc_hd__ }
C {devices/lab_pin.sym} 1790 -1960 0 0 {name=p371 lab=A1}
C {devices/lab_pin.sym} 1790 -1920 0 0 {name=p372 lab=A2}
C {devices/lab_pin.sym} 1790 -1880 0 0 {name=p373 lab=B1}
C {devices/lab_pin.sym} 1790 -1840 0 0 {name=p374 lab=C1}
C {devices/lab_pin.sym} 1790 -1800 0 0 {name=p375 lab=D1}
C {devices/lab_pin.sym} 1950 -1880 0 1 {name=p376 lab=Y}
C {sky130_stdcells/o2bb2a_1.sym} 1870 -2100 0 0 {name=x89 VGND=VGND VNB=VNB VPB=VPB VPWR=VPWR prefix=sky130_fd_sc_hd__ }
C {devices/lab_pin.sym} 1790 -2160 0 0 {name=p377 lab=A1_N}
C {devices/lab_pin.sym} 1790 -2120 0 0 {name=p378 lab=A2_N}
C {devices/lab_pin.sym} 1790 -2080 0 0 {name=p379 lab=B1}
C {devices/lab_pin.sym} 1790 -2040 0 0 {name=p380 lab=B2}
C {devices/lab_pin.sym} 1950 -2100 0 1 {name=p381 lab=X}
C {sky130_stdcells/o2bb2ai_1.sym} 1870 -2300 0 0 {name=x90 VGND=VGND VNB=VNB VPB=VPB VPWR=VPWR prefix=sky130_fd_sc_hd__ }
C {devices/lab_pin.sym} 1790 -2360 0 0 {name=p382 lab=A1_N}
C {devices/lab_pin.sym} 1790 -2320 0 0 {name=p383 lab=A2_N}
C {devices/lab_pin.sym} 1790 -2280 0 0 {name=p384 lab=B1}
C {devices/lab_pin.sym} 1790 -2240 0 0 {name=p385 lab=B2}
C {devices/lab_pin.sym} 1950 -2300 0 1 {name=p386 lab=Y}
C {sky130_stdcells/o32a_1.sym} 2195 -2370 0 0 {name=x91 VGND=VGND VNB=VNB VPB=VPB VPWR=VPWR prefix=sky130_fd_sc_hd__ }
C {devices/lab_pin.sym} 2115 -2450 0 0 {name=p387 lab=A1}
C {devices/lab_pin.sym} 2115 -2410 0 0 {name=p388 lab=A2}
C {devices/lab_pin.sym} 2115 -2370 0 0 {name=p389 lab=A3}
C {devices/lab_pin.sym} 2115 -2330 0 0 {name=p390 lab=B1}
C {devices/lab_pin.sym} 2115 -2290 0 0 {name=p391 lab=B2}
C {devices/lab_pin.sym} 2275 -2370 0 1 {name=p392 lab=X}
C {sky130_stdcells/o32ai_1.sym} 2195 -2140 0 0 {name=x92 VGND=VGND VNB=VNB VPB=VPB VPWR=VPWR prefix=sky130_fd_sc_hd__ }
C {devices/lab_pin.sym} 2115 -2220 0 0 {name=p393 lab=A1}
C {devices/lab_pin.sym} 2115 -2180 0 0 {name=p394 lab=A2}
C {devices/lab_pin.sym} 2115 -2140 0 0 {name=p395 lab=A3}
C {devices/lab_pin.sym} 2115 -2100 0 0 {name=p396 lab=B1}
C {devices/lab_pin.sym} 2115 -2060 0 0 {name=p397 lab=B2}
C {devices/lab_pin.sym} 2275 -2140 0 1 {name=p398 lab=Y}
C {sky130_stdcells/o41a_1.sym} 2185 -1770 0 0 {name=x93 VGND=VGND VNB=VNB VPB=VPB VPWR=VPWR prefix=sky130_fd_sc_hd__ }
C {devices/lab_pin.sym} 2105 -1850 0 0 {name=p399 lab=A1}
C {devices/lab_pin.sym} 2105 -1810 0 0 {name=p400 lab=A2}
C {devices/lab_pin.sym} 2105 -1770 0 0 {name=p401 lab=A3}
C {devices/lab_pin.sym} 2105 -1730 0 0 {name=p402 lab=A4}
C {devices/lab_pin.sym} 2105 -1690 0 0 {name=p403 lab=B1}
C {devices/lab_pin.sym} 2265 -1770 0 1 {name=p404 lab=X}
C {sky130_stdcells/o41ai_1.sym} 2185 -1560 0 0 {name=x94 VGND=VGND VNB=VNB VPB=VPB VPWR=VPWR prefix=sky130_fd_sc_hd__ }
C {devices/lab_pin.sym} 2105 -1640 0 0 {name=p405 lab=A1}
C {devices/lab_pin.sym} 2105 -1600 0 0 {name=p406 lab=A2}
C {devices/lab_pin.sym} 2105 -1560 0 0 {name=p407 lab=A3}
C {devices/lab_pin.sym} 2105 -1520 0 0 {name=p408 lab=A4}
C {devices/lab_pin.sym} 2105 -1480 0 0 {name=p409 lab=B1}
C {devices/lab_pin.sym} 2265 -1560 0 1 {name=p410 lab=Y}
C {sky130_stdcells/or2_1.sym} 2150 -1295 0 0 {name=x95 VGND=VGND VNB=VNB VPB=VPB VPWR=VPWR prefix=sky130_fd_sc_hd__ }
C {devices/lab_pin.sym} 2090 -1315 0 0 {name=p411 lab=A}
C {devices/lab_pin.sym} 2090 -1275 0 0 {name=p412 lab=B}
C {devices/lab_pin.sym} 2210 -1295 0 1 {name=p413 lab=X}
C {sky130_stdcells/or2b_1.sym} 2155 -1160 0 0 {name=x96 VGND=VGND VNB=VNB VPB=VPB VPWR=VPWR prefix=sky130_fd_sc_hd__ }
C {devices/lab_pin.sym} 2095 -1180 0 0 {name=p414 lab=A}
C {devices/lab_pin.sym} 2095 -1140 0 0 {name=p415 lab=B_N}
C {devices/lab_pin.sym} 2215 -1160 0 1 {name=p416 lab=X}
C {sky130_stdcells/or3_1.sym} 2155 -1020 0 0 {name=x97 VGND=VGND VNB=VNB VPB=VPB VPWR=VPWR prefix=sky130_fd_sc_hd__ }
C {devices/lab_pin.sym} 2095 -1060 0 0 {name=p417 lab=A}
C {devices/lab_pin.sym} 2095 -1020 0 0 {name=p418 lab=B}
C {devices/lab_pin.sym} 2095 -980 0 0 {name=p419 lab=C}
C {devices/lab_pin.sym} 2215 -1020 0 1 {name=p420 lab=X}
C {sky130_stdcells/or3b_1.sym} 2155 -860 0 0 {name=x98 VGND=VGND VNB=VNB VPB=VPB VPWR=VPWR prefix=sky130_fd_sc_hd__ }
C {devices/lab_pin.sym} 2095 -900 0 0 {name=p421 lab=A}
C {devices/lab_pin.sym} 2095 -860 0 0 {name=p422 lab=B}
C {devices/lab_pin.sym} 2095 -820 0 0 {name=p423 lab=C_N}
C {devices/lab_pin.sym} 2215 -860 0 1 {name=p424 lab=X}
C {sky130_stdcells/or4_1.sym} 2155 -680 0 0 {name=x99 VGND=VGND VNB=VNB VPB=VPB VPWR=VPWR prefix=sky130_fd_sc_hd__ }
C {devices/lab_pin.sym} 2095 -740 0 0 {name=p425 lab=A}
C {devices/lab_pin.sym} 2095 -700 0 0 {name=p426 lab=B}
C {devices/lab_pin.sym} 2095 -660 0 0 {name=p427 lab=C}
C {devices/lab_pin.sym} 2095 -620 0 0 {name=p428 lab=D}
C {devices/lab_pin.sym} 2215 -680 0 1 {name=p429 lab=X}
C {sky130_stdcells/or4b_1.sym} 2135 -480 0 0 {name=x100 VGND=VGND VNB=VNB VPB=VPB VPWR=VPWR prefix=sky130_fd_sc_hd__ }
C {devices/lab_pin.sym} 2075 -540 0 0 {name=p430 lab=A}
C {devices/lab_pin.sym} 2075 -500 0 0 {name=p431 lab=B}
C {devices/lab_pin.sym} 2075 -460 0 0 {name=p432 lab=C}
C {devices/lab_pin.sym} 2075 -420 0 0 {name=p433 lab=D_N}
C {devices/lab_pin.sym} 2195 -480 0 1 {name=p434 lab=X}
C {sky130_stdcells/or4bb_1.sym} 2135 -300 0 0 {name=x101 VGND=VGND VNB=VNB VPB=VPB VPWR=VPWR prefix=sky130_fd_sc_hd__ }
C {devices/lab_pin.sym} 2075 -360 0 0 {name=p435 lab=A}
C {devices/lab_pin.sym} 2075 -320 0 0 {name=p436 lab=B}
C {devices/lab_pin.sym} 2075 -280 0 0 {name=p437 lab=C_N}
C {devices/lab_pin.sym} 2075 -240 0 0 {name=p438 lab=D_N}
C {devices/lab_pin.sym} 2195 -300 0 1 {name=p439 lab=X}
C {sky130_stdcells/xnor2_1.sym} 2460 -2290 0 0 {name=x102 VGND=VGND VNB=VNB VPB=VPB VPWR=VPWR prefix=sky130_fd_sc_hd__ }
C {devices/lab_pin.sym} 2400 -2310 0 0 {name=p440 lab=A}
C {devices/lab_pin.sym} 2400 -2270 0 0 {name=p441 lab=B}
C {devices/lab_pin.sym} 2520 -2290 0 1 {name=p442 lab=Y}
C {sky130_stdcells/xnor3_1.sym} 2460 -2160 0 0 {name=x103 VGND=VGND VNB=VNB VPB=VPB VPWR=VPWR prefix=sky130_fd_sc_hd__ }
C {devices/lab_pin.sym} 2400 -2200 0 0 {name=p443 lab=A}
C {devices/lab_pin.sym} 2400 -2160 0 0 {name=p444 lab=B}
C {devices/lab_pin.sym} 2520 -2160 0 1 {name=p445 lab=X}
C {devices/lab_pin.sym} 2400 -2120 0 0 {name=p446 lab=C}
C {sky130_stdcells/xor2_1.sym} 2460 -2040 0 0 {name=x104 VGND=VGND VNB=VNB VPB=VPB VPWR=VPWR prefix=sky130_fd_sc_hd__ }
C {devices/lab_pin.sym} 2400 -2060 0 0 {name=p447 lab=A}
C {devices/lab_pin.sym} 2400 -2020 0 0 {name=p448 lab=B}
C {devices/lab_pin.sym} 2520 -2040 0 1 {name=p449 lab=X}
C {sky130_stdcells/xor3_1.sym} 2460 -1920 0 0 {name=x105 VGND=VGND VNB=VNB VPB=VPB VPWR=VPWR prefix=sky130_fd_sc_hd__ }
C {devices/lab_pin.sym} 2400 -1960 0 0 {name=p450 lab=A}
C {devices/lab_pin.sym} 2400 -1920 0 0 {name=p451 lab=B}
C {devices/lab_pin.sym} 2520 -1920 0 1 {name=p452 lab=X}
C {devices/lab_pin.sym} 2400 -1880 0 0 {name=p453 lab=C}
C {sky130_stdcells/sdfbbn_1.sym} 2500 -300 0 0 {name=x106 VGND=VGND VNB=VNB VPB=VPB VPWR=VPWR prefix=sky130_fd_sc_hd__ }
C {sky130_stdcells/sdfbbp_1.sym} 2500 -450 0 0 {name=x107 VGND=VGND VNB=VNB VPB=VPB VPWR=VPWR prefix=sky130_fd_sc_hd__ }
C {sky130_stdcells/sdfrbp_1.sym} 2500 -590 0 0 {name=x108 VGND=VGND VNB=VNB VPB=VPB VPWR=VPWR prefix=sky130_fd_sc_hd__ }
C {sky130_stdcells/sdfrtn_1.sym} 2500 -710 0 0 {name=x109 VGND=VGND VNB=VNB VPB=VPB VPWR=VPWR prefix=sky130_fd_sc_hd__ }
C {sky130_stdcells/sdfrtp_1.sym} 2500 -830 0 0 {name=x110 VGND=VGND VNB=VNB VPB=VPB VPWR=VPWR prefix=sky130_fd_sc_hd__ }
C {sky130_stdcells/sdfsbp_1.sym} 2500 -960 0 0 {name=x111 VGND=VGND VNB=VNB VPB=VPB VPWR=VPWR prefix=sky130_fd_sc_hd__ }
C {sky130_stdcells/sdfstp_1.sym} 2500 -1090 0 0 {name=x112 VGND=VGND VNB=VNB VPB=VPB VPWR=VPWR prefix=sky130_fd_sc_hd__ }
C {sky130_stdcells/sdfxbp_1.sym} 2500 -1200 0 0 {name=x113 VGND=VGND VNB=VNB VPB=VPB VPWR=VPWR prefix=sky130_fd_sc_hd__ }
C {sky130_stdcells/sdlclkp_1.sym} 2500 -1390 0 0 {name=x114 VGND=VGND VNB=VNB VPB=VPB VPWR=VPWR prefix=sky130_fd_sc_hd__ }
C {sky130_stdcells/sedfxbp_1.sym} 2500 -1490 0 0 {name=x115 VGND=VGND VNB=VNB VPB=VPB VPWR=VPWR prefix=sky130_fd_sc_hd__ }
C {sky130_stdcells/sedfxtp_1.sym} 2500 -1610 0 0 {name=x116 VGND=VGND VNB=VNB VPB=VPB VPWR=VPWR prefix=sky130_fd_sc_hd__ }
C {sky130_stdcells/sdfxtp_1.sym} 2500 -1300 0 0 {name=x117 VGND=VGND VNB=VNB VPB=VPB VPWR=VPWR prefix=sky130_fd_sc_hd__ }
C {sky130_stdcells/dfbbn_1.sym} 2860 -280 0 0 {name=x118 VGND=VGND VNB=VNB VPB=VPB VPWR=VPWR prefix=sky130_fd_sc_hd__ }
C {sky130_stdcells/dfbbp_1.sym} 2860 -380 0 0 {name=x119 VGND=VGND VNB=VNB VPB=VPB VPWR=VPWR prefix=sky130_fd_sc_hd__ }
C {sky130_stdcells/dfrtp_1.sym} 2860 -650 0 0 {name=x121 VGND=VGND VNB=VNB VPB=VPB VPWR=VPWR prefix=sky130_fd_sc_hd__ }
C {sky130_stdcells/dfsbp_1.sym} 2860 -730 0 0 {name=x122 VGND=VGND VNB=VNB VPB=VPB VPWR=VPWR prefix=sky130_fd_sc_hd__ }
C {sky130_stdcells/dfstp_1.sym} 2860 -800 0 0 {name=x123 VGND=VGND VNB=VNB VPB=VPB VPWR=VPWR prefix=sky130_fd_sc_hd__ }
C {sky130_stdcells/dfxbp_1.sym} 2860 -870 0 0 {name=x124 VGND=VGND VNB=VNB VPB=VPB VPWR=VPWR prefix=sky130_fd_sc_hd__ }
C {sky130_stdcells/dlclkp_1.sym} 2860 -985 0 0 {name=x125 VGND=VGND VNB=VNB VPB=VPB VPWR=VPWR prefix=sky130_fd_sc_hd__ }
C {sky130_stdcells/dlrbn_1.sym} 2860 -1055 0 0 {name=x126 VGND=VGND VNB=VNB VPB=VPB VPWR=VPWR prefix=sky130_fd_sc_hd__ }
C {sky130_stdcells/dlrbp_1.sym} 2860 -1135 0 0 {name=x127 VGND=VGND VNB=VNB VPB=VPB VPWR=VPWR prefix=sky130_fd_sc_hd__ }
C {sky130_stdcells/dlrtn_1.sym} 2860 -1215 0 0 {name=x128 VGND=VGND VNB=VNB VPB=VPB VPWR=VPWR prefix=sky130_fd_sc_hd__ }
C {sky130_stdcells/dlrtp_1.sym} 2860 -1295 0 0 {name=x129 VGND=VGND VNB=VNB VPB=VPB VPWR=VPWR prefix=sky130_fd_sc_hd__ }
C {sky130_stdcells/dlxbn_1.sym} 2860 -1365 0 0 {name=x130 VGND=VGND VNB=VNB VPB=VPB VPWR=VPWR prefix=sky130_fd_sc_hd__ }
C {sky130_stdcells/dlxtp_1.sym} 2860 -1425 0 0 {name=x131 VGND=VGND VNB=VNB VPB=VPB VPWR=VPWR prefix=sky130_fd_sc_hd__ }
C {sky130_stdcells/edfxbp_1.sym} 2860 -1595 0 0 {name=x132 VGND=VGND VNB=VNB VPB=VPB VPWR=VPWR prefix=sky130_fd_sc_hd__ }
C {sky130_stdcells/edfxtp_1.sym} 2860 -1675 0 0 {name=x133 VGND=VGND VNB=VNB VPB=VPB VPWR=VPWR prefix=sky130_fd_sc_hd__ }
C {sky130_stdcells/fill_1.sym} 3250 -1100 0 0 {name=x134 VGND=VGND VNB=VNB VPB=VPB VPWR=VPWR prefix=sky130_fd_sc_hd__ }
C {sky130_stdcells/dfrbp_1.sym} 2860 -480 0 0 {name=x120 VGND=VGND VNB=VNB VPB=VPB VPWR=VPWR prefix=sky130_fd_sc_hd__ }
C {sky130_stdcells/dfrtn_1.sym} 2860 -560 0 0 {name=x135 VGND=VGND VNB=VNB VPB=VPB VPWR=VPWR prefix=sky130_fd_sc_hd__ }
C {sky130_stdcells/dfxtp_1.sym} 2860 -920 0 0 {name=x136 VGND=VGND VNB=VNB VPB=VPB VPWR=VPWR prefix=sky130_fd_sc_hd__ }
C {sky130_stdcells/dlxtn_1.sym} 2860 -1485 0 0 {name=x137 VGND=VGND VNB=VNB VPB=VPB VPWR=VPWR prefix=sky130_fd_sc_hd__ }
C {sky130_stdcells/dlxtp_1.sym} 2860 -1535 0 0 {name=x138 VGND=VGND VNB=VNB VPB=VPB VPWR=VPWR prefix=sky130_fd_sc_hd__ }
C {sky130_stdcells/tap_1.sym} 3250 -810 0 0 {name=x139 VGND=VGND VNB=VNB VPB=VPB VPWR=VPWR prefix=sky130_fd_sc_hd__ }
C {sky130_stdcells/tapvgnd_1.sym} 3250 -900 0 0 {name=x141 VGND=VGND VPB=VPB VPWR=VPWR prefix=sky130_fd_sc_hd__ }
C {sky130_stdcells/tapvgnd2_1.sym} 3250 -940 0 0 {name=x142 VGND=VGND VPB=VPB VPWR=VPWR prefix=sky130_fd_sc_hd__ }
C {sky130_stdcells/tapvpwrvgnd_1.sym} 3250 -980 0 0 {name=x143 VGND=VGND VPWR=VPWR prefix=sky130_fd_sc_hd__ }
C {sky130_stdcells/lpflow_bleeder_1.sym} 3250 -1030 0 0 {name=x144 VGND=VGND VNB=VNB VPB=VPB VPWR=VPWR prefix=sky130_fd_sc_hd__ }
C {sky130_stdcells/lpflow_clkbufkapwr_1.sym} 3250 -275 0 0 {name=x145 VGND=VGND VNB=VNB VPB=VPB VPWR=VPWR prefix=sky130_fd_sc_hd__ }
C {sky130_stdcells/lpflow_clkinvkapwr_1.sym} 3250 -370 0 0 {name=x146 VGND=VGND VNB=VNB VPB=VPB VPWR=VPWR prefix=sky130_fd_sc_hd__ }
C {sky130_stdcells/lpflow_inputiso0n_1.sym} 3250 -470 0 0 {name=x147 VGND=VGND VNB=VNB VPB=VPB VPWR=VPWR prefix=sky130_fd_sc_hd__ }
C {sky130_stdcells/lpflow_inputiso0p_1.sym} 3250 -555 0 0 {name=x148 VGND=VGND VNB=VNB VPB=VPB VPWR=VPWR prefix=sky130_fd_sc_hd__ }
C {sky130_stdcells/lpflow_inputiso1n_1.sym} 3250 -640 0 0 {name=x149 VGND=VGND VNB=VNB VPB=VPB VPWR=VPWR prefix=sky130_fd_sc_hd__ }
C {sky130_stdcells/lpflow_inputiso1p_1.sym} 3250 -725 0 0 {name=x150 VGND=VGND VNB=VNB VPB=VPB VPWR=VPWR prefix=sky130_fd_sc_hd__ }
C {sky130_stdcells/lpflow_inputisolatch_1.sym} 3250 -1415 0 0 {name=x151 VGND=VGND VNB=VNB VPB=VPB VPWR=VPWR prefix=sky130_fd_sc_hd__ }
C {sky130_stdcells/lpflow_isobufsrc_1.sym} 3250 -1345 0 0 {name=x152 VGND=VGND VNB=VNB VPB=VPB VPWR=VPWR prefix=sky130_fd_sc_hd__ }
C {sky130_stdcells/lpflow_lsbuf_lh_isowell_tap_1.sym} 3250 -1235 0 0 {name=x153 VGND=VGND VPB=VPB VPWR=VPWR prefix=sky130_fd_sc_hd__ }
C {sky130_stdcells/lpflow_lsbuf_lh_hl_isowell_tap_1.sym} 3250 -1165 0 0 {name=x154 VGND=VGND VPB=VPB VPWR=VPWR prefix=sky130_fd_sc_hd__ }
C {devices/lab_pin.sym} 720 -1770 0 0 {name=p454 lab=A_N}
C {devices/lab_pin.sym} 2410 -350 0 0 {name=p179 lab=CLK_N}
C {devices/lab_pin.sym} 2410 -330 0 0 {name=p455 lab=D}
C {devices/lab_pin.sym} 2410 -310 0 0 {name=p456 lab=RESET_B}
C {devices/lab_pin.sym} 2410 -290 0 0 {name=p457 lab=SCD}
C {devices/lab_pin.sym} 2410 -270 0 0 {name=p458 lab=SCE}
C {devices/lab_pin.sym} 2410 -250 0 0 {name=p459 lab=SET_B}
C {devices/lab_pin.sym} 2590 -350 0 1 {name=p460 lab=Q}
C {devices/lab_pin.sym} 2590 -330 0 1 {name=p461 lab=Q_N}
C {devices/lab_pin.sym} 2410 -500 0 0 {name=p462 lab=CLK}
C {devices/lab_pin.sym} 2410 -480 0 0 {name=p463 lab=D}
C {devices/lab_pin.sym} 2410 -460 0 0 {name=p464 lab=RESET_B}
C {devices/lab_pin.sym} 2410 -440 0 0 {name=p465 lab=SCD}
C {devices/lab_pin.sym} 2410 -420 0 0 {name=p466 lab=SCE}
C {devices/lab_pin.sym} 2410 -400 0 0 {name=p467 lab=SET_B}
C {devices/lab_pin.sym} 2590 -500 0 1 {name=p468 lab=Q}
C {devices/lab_pin.sym} 2590 -480 0 1 {name=p469 lab=Q_N}
C {devices/lab_pin.sym} 2410 -630 0 0 {name=p470 lab=CLK}
C {devices/lab_pin.sym} 2410 -610 0 0 {name=p471 lab=D}
C {devices/lab_pin.sym} 2410 -590 0 0 {name=p472 lab=RESET_B}
C {devices/lab_pin.sym} 2410 -570 0 0 {name=p473 lab=SCD}
C {devices/lab_pin.sym} 2410 -550 0 0 {name=p474 lab=SCE}
C {devices/lab_pin.sym} 2590 -630 0 1 {name=p475 lab=Q}
C {devices/lab_pin.sym} 2590 -610 0 1 {name=p476 lab=Q_N}
C {devices/lab_pin.sym} 2410 -750 0 0 {name=p477 lab=CLK_N}
C {devices/lab_pin.sym} 2410 -730 0 0 {name=p478 lab=D}
C {devices/lab_pin.sym} 2410 -710 0 0 {name=p479 lab=RESET_B}
C {devices/lab_pin.sym} 2410 -690 0 0 {name=p480 lab=SCD}
C {devices/lab_pin.sym} 2410 -670 0 0 {name=p481 lab=SCE}
C {devices/lab_pin.sym} 2590 -750 0 1 {name=p482 lab=Q}
C {devices/lab_pin.sym} 2410 -870 0 0 {name=p483 lab=CLK}
C {devices/lab_pin.sym} 2410 -850 0 0 {name=p484 lab=D}
C {devices/lab_pin.sym} 2410 -830 0 0 {name=p485 lab=RESET_B}
C {devices/lab_pin.sym} 2410 -810 0 0 {name=p486 lab=SCD}
C {devices/lab_pin.sym} 2410 -790 0 0 {name=p487 lab=SCE}
C {devices/lab_pin.sym} 2590 -870 0 1 {name=p488 lab=Q}
C {devices/lab_pin.sym} 2410 -1000 0 0 {name=p489 lab=CLK}
C {devices/lab_pin.sym} 2410 -980 0 0 {name=p490 lab=D}
C {devices/lab_pin.sym} 2410 -960 0 0 {name=p491 lab=SCD}
C {devices/lab_pin.sym} 2410 -940 0 0 {name=p492 lab=SCE}
C {devices/lab_pin.sym} 2410 -920 0 0 {name=p493 lab=SET_B}
C {devices/lab_pin.sym} 2590 -1000 0 1 {name=p494 lab=Q}
C {devices/lab_pin.sym} 2590 -980 0 1 {name=p495 lab=Q_N}
C {devices/lab_pin.sym} 2410 -1130 0 0 {name=p496 lab=CLK}
C {devices/lab_pin.sym} 2410 -1110 0 0 {name=p497 lab=D}
C {devices/lab_pin.sym} 2410 -1090 0 0 {name=p498 lab=SCD}
C {devices/lab_pin.sym} 2410 -1070 0 0 {name=p499 lab=SCE}
C {devices/lab_pin.sym} 2410 -1050 0 0 {name=p500 lab=SET_B}
C {devices/lab_pin.sym} 2590 -1130 0 1 {name=p501 lab=Q}
C {devices/lab_pin.sym} 2410 -1230 0 0 {name=p502 lab=CLK}
C {devices/lab_pin.sym} 2410 -1210 0 0 {name=p503 lab=D}
C {devices/lab_pin.sym} 2410 -1190 0 0 {name=p504 lab=SCD}
C {devices/lab_pin.sym} 2410 -1170 0 0 {name=p505 lab=SCE}
C {devices/lab_pin.sym} 2590 -1230 0 1 {name=p506 lab=Q}
C {devices/lab_pin.sym} 2590 -1210 0 1 {name=p507 lab=Q_N}
C {devices/lab_pin.sym} 2410 -1410 0 0 {name=p508 lab=CLK}
C {devices/lab_pin.sym} 2410 -1390 0 0 {name=p509 lab=GATE}
C {devices/lab_pin.sym} 2410 -1370 0 0 {name=p510 lab=SCE}
C {devices/lab_pin.sym} 2590 -1410 0 1 {name=p511 lab=GCLK}
C {devices/lab_pin.sym} 2410 -1530 0 0 {name=p512 lab=CLK}
C {devices/lab_pin.sym} 2410 -1510 0 0 {name=p513 lab=D}
C {devices/lab_pin.sym} 2410 -1490 0 0 {name=p514 lab=DE}
C {devices/lab_pin.sym} 2410 -1470 0 0 {name=p515 lab=SCD}
C {devices/lab_pin.sym} 2410 -1450 0 0 {name=p516 lab=SCE}
C {devices/lab_pin.sym} 2590 -1530 0 1 {name=p517 lab=Q}
C {devices/lab_pin.sym} 2590 -1510 0 1 {name=p518 lab=Q_N}
C {devices/lab_pin.sym} 2410 -1650 0 0 {name=p519 lab=CLK}
C {devices/lab_pin.sym} 2410 -1630 0 0 {name=p520 lab=D}
C {devices/lab_pin.sym} 2410 -1610 0 0 {name=p521 lab=DE}
C {devices/lab_pin.sym} 2410 -1590 0 0 {name=p522 lab=SCD}
C {devices/lab_pin.sym} 2410 -1570 0 0 {name=p523 lab=SCE}
C {devices/lab_pin.sym} 2590 -1650 0 1 {name=p524 lab=Q}
C {devices/lab_pin.sym} 2410 -1330 0 0 {name=p525 lab=CLK}
C {devices/lab_pin.sym} 2410 -1310 0 0 {name=p526 lab=D}
C {devices/lab_pin.sym} 2410 -1290 0 0 {name=p527 lab=SCD}
C {devices/lab_pin.sym} 2410 -1270 0 0 {name=p528 lab=SCE}
C {devices/lab_pin.sym} 2590 -1330 0 1 {name=p529 lab=Q}
C {devices/lab_pin.sym} 2770 -310 0 0 {name=p530 lab=CLK_N}
C {devices/lab_pin.sym} 2770 -290 0 0 {name=p531 lab=D}
C {devices/lab_pin.sym} 2770 -270 0 0 {name=p532 lab=RESET_B}
C {devices/lab_pin.sym} 2770 -250 0 0 {name=p533 lab=SET_B}
C {devices/lab_pin.sym} 2950 -310 0 1 {name=p534 lab=Q}
C {devices/lab_pin.sym} 2950 -290 0 1 {name=p535 lab=Q_N}
C {devices/lab_pin.sym} 2770 -410 0 0 {name=p536 lab=CLK}
C {devices/lab_pin.sym} 2770 -390 0 0 {name=p537 lab=D}
C {devices/lab_pin.sym} 2770 -370 0 0 {name=p538 lab=RESET_B}
C {devices/lab_pin.sym} 2770 -350 0 0 {name=p539 lab=SET_B}
C {devices/lab_pin.sym} 2950 -410 0 1 {name=p540 lab=Q}
C {devices/lab_pin.sym} 2950 -390 0 1 {name=p541 lab=Q_N}
C {devices/lab_pin.sym} 2770 -670 0 0 {name=p542 lab=CLK}
C {devices/lab_pin.sym} 2770 -650 0 0 {name=p543 lab=D}
C {devices/lab_pin.sym} 2770 -630 0 0 {name=p544 lab=RESET_B}
C {devices/lab_pin.sym} 2950 -670 0 1 {name=p545 lab=Q}
C {devices/lab_pin.sym} 2770 -750 0 0 {name=p546 lab=CLK}
C {devices/lab_pin.sym} 2770 -730 0 0 {name=p547 lab=D}
C {devices/lab_pin.sym} 2770 -710 0 0 {name=p548 lab=SET_B}
C {devices/lab_pin.sym} 2950 -750 0 1 {name=p549 lab=Q}
C {devices/lab_pin.sym} 2950 -730 0 1 {name=p550 lab=Q_N}
C {devices/lab_pin.sym} 2770 -820 0 0 {name=p551 lab=CLK}
C {devices/lab_pin.sym} 2770 -800 0 0 {name=p552 lab=D}
C {devices/lab_pin.sym} 2770 -780 0 0 {name=p553 lab=SET_B}
C {devices/lab_pin.sym} 2950 -820 0 1 {name=p554 lab=Q}
C {devices/lab_pin.sym} 2770 -880 0 0 {name=p555 lab=CLK}
C {devices/lab_pin.sym} 2770 -860 0 0 {name=p556 lab=D}
C {devices/lab_pin.sym} 2950 -880 0 1 {name=p557 lab=Q}
C {devices/lab_pin.sym} 2950 -860 0 1 {name=p558 lab=Q_N}
C {devices/lab_pin.sym} 2770 -995 0 0 {name=p559 lab=CLK}
C {devices/lab_pin.sym} 2770 -975 0 0 {name=p560 lab=GATE}
C {devices/lab_pin.sym} 2950 -995 0 1 {name=p561 lab=GCLK}
C {devices/lab_pin.sym} 2770 -1075 0 0 {name=p562 lab=D}
C {devices/lab_pin.sym} 2770 -1055 0 0 {name=p563 lab=GATE_N}
C {devices/lab_pin.sym} 2770 -1035 0 0 {name=p564 lab=RESET_B}
C {devices/lab_pin.sym} 2950 -1075 0 1 {name=p565 lab=Q}
C {devices/lab_pin.sym} 2950 -1055 0 1 {name=p566 lab=Q_N}
C {devices/lab_pin.sym} 2770 -1155 0 0 {name=p567 lab=D}
C {devices/lab_pin.sym} 2770 -1135 0 0 {name=p568 lab=GATE}
C {devices/lab_pin.sym} 2770 -1115 0 0 {name=p569 lab=RESET_B}
C {devices/lab_pin.sym} 2950 -1155 0 1 {name=p570 lab=Q}
C {devices/lab_pin.sym} 2950 -1135 0 1 {name=p571 lab=Q_N}
C {devices/lab_pin.sym} 2770 -1235 0 0 {name=p572 lab=D}
C {devices/lab_pin.sym} 2770 -1215 0 0 {name=p573 lab=GATE_N}
C {devices/lab_pin.sym} 2770 -1195 0 0 {name=p574 lab=RESET_B}
C {devices/lab_pin.sym} 2950 -1235 0 1 {name=p575 lab=Q}
C {devices/lab_pin.sym} 2770 -1315 0 0 {name=p576 lab=D}
C {devices/lab_pin.sym} 2770 -1295 0 0 {name=p577 lab=GATE}
C {devices/lab_pin.sym} 2770 -1275 0 0 {name=p578 lab=RESET_B}
C {devices/lab_pin.sym} 2950 -1315 0 1 {name=p579 lab=Q}
C {devices/lab_pin.sym} 2770 -1375 0 0 {name=p580 lab=D}
C {devices/lab_pin.sym} 2770 -1355 0 0 {name=p581 lab=GATE_N}
C {devices/lab_pin.sym} 2950 -1375 0 1 {name=p582 lab=Q}
C {devices/lab_pin.sym} 2950 -1355 0 1 {name=p583 lab=Q_N}
C {devices/lab_pin.sym} 2770 -1435 0 0 {name=p584 lab=D}
C {devices/lab_pin.sym} 2770 -1415 0 0 {name=p585 lab=GATE}
C {devices/lab_pin.sym} 2950 -1435 0 1 {name=p586 lab=Q}
C {devices/lab_pin.sym} 2770 -1615 0 0 {name=p587 lab=CLK}
C {devices/lab_pin.sym} 2770 -1595 0 0 {name=p588 lab=D}
C {devices/lab_pin.sym} 2770 -1575 0 0 {name=p589 lab=DE}
C {devices/lab_pin.sym} 2950 -1615 0 1 {name=p590 lab=Q}
C {devices/lab_pin.sym} 2950 -1595 0 1 {name=p591 lab=Q_N}
C {devices/lab_pin.sym} 2770 -1695 0 0 {name=p592 lab=CLK}
C {devices/lab_pin.sym} 2770 -1675 0 0 {name=p593 lab=D}
C {devices/lab_pin.sym} 2770 -1655 0 0 {name=p594 lab=DE}
C {devices/lab_pin.sym} 2950 -1695 0 1 {name=p595 lab=Q}
C {devices/lab_pin.sym} 2770 -500 0 0 {name=p596 lab=CLK}
C {devices/lab_pin.sym} 2770 -480 0 0 {name=p597 lab=D}
C {devices/lab_pin.sym} 2770 -460 0 0 {name=p598 lab=RESET_B}
C {devices/lab_pin.sym} 2950 -500 0 1 {name=p599 lab=Q}
C {devices/lab_pin.sym} 2950 -480 0 1 {name=p600 lab=Q_N}
C {devices/lab_pin.sym} 2770 -580 0 0 {name=p601 lab=CLK_N}
C {devices/lab_pin.sym} 2770 -560 0 0 {name=p602 lab=D}
C {devices/lab_pin.sym} 2770 -540 0 0 {name=p603 lab=RESET_B}
C {devices/lab_pin.sym} 2950 -580 0 1 {name=p604 lab=Q}
C {devices/lab_pin.sym} 2770 -930 0 0 {name=p605 lab=CLK}
C {devices/lab_pin.sym} 2770 -910 0 0 {name=p606 lab=D}
C {devices/lab_pin.sym} 2950 -930 0 1 {name=p607 lab=Q}
C {devices/lab_pin.sym} 2770 -1495 0 0 {name=p608 lab=D}
C {devices/lab_pin.sym} 2770 -1475 0 0 {name=p609 lab=GATE_N}
C {devices/lab_pin.sym} 2950 -1495 0 1 {name=p610 lab=Q}
C {devices/lab_pin.sym} 2770 -1545 0 0 {name=p611 lab=D}
C {devices/lab_pin.sym} 2770 -1525 0 0 {name=p612 lab=GATE}
C {devices/lab_pin.sym} 2950 -1545 0 1 {name=p613 lab=Q}
C {devices/lab_pin.sym} 3160 -1030 0 0 {name=p614 lab=SHORT}
C {devices/lab_pin.sym} 3160 -285 0 0 {name=p615 lab=A}
C {devices/lab_pin.sym} 3160 -265 0 0 {name=p616 lab=KAPWR}
C {devices/lab_pin.sym} 3340 -285 0 1 {name=p617 lab=X}
C {devices/lab_pin.sym} 3160 -380 0 0 {name=p618 lab=A}
C {devices/lab_pin.sym} 3160 -360 0 0 {name=p619 lab=KAPWR}
C {devices/lab_pin.sym} 3340 -380 0 1 {name=p620 lab=Y}
C {devices/lab_pin.sym} 3160 -480 0 0 {name=p621 lab=A}
C {devices/lab_pin.sym} 3160 -460 0 0 {name=p622 lab=SLEEP_B}
C {devices/lab_pin.sym} 3340 -480 0 1 {name=p623 lab=X}
C {devices/lab_pin.sym} 3160 -565 0 0 {name=p624 lab=A}
C {devices/lab_pin.sym} 3160 -545 0 0 {name=p625 lab=SLEEP}
C {devices/lab_pin.sym} 3340 -565 0 1 {name=p626 lab=X}
C {devices/lab_pin.sym} 3160 -650 0 0 {name=p627 lab=A}
C {devices/lab_pin.sym} 3160 -630 0 0 {name=p628 lab=SLEEP_B}
C {devices/lab_pin.sym} 3340 -650 0 1 {name=p629 lab=X}
C {devices/lab_pin.sym} 3160 -735 0 0 {name=p630 lab=A}
C {devices/lab_pin.sym} 3160 -715 0 0 {name=p631 lab=SLEEP}
C {devices/lab_pin.sym} 3340 -735 0 1 {name=p632 lab=X}
C {devices/lab_pin.sym} 3160 -1425 0 0 {name=p633 lab=D}
C {devices/lab_pin.sym} 3160 -1405 0 0 {name=p634 lab=SLEEP_B}
C {devices/lab_pin.sym} 3340 -1425 0 1 {name=p635 lab=Q}
C {devices/lab_pin.sym} 3160 -1355 0 0 {name=p636 lab=A}
C {devices/lab_pin.sym} 3160 -1335 0 0 {name=p637 lab=SLEEP}
C {devices/lab_pin.sym} 3340 -1355 0 1 {name=p638 lab=X}
C {devices/lab_pin.sym} 3160 -1245 0 0 {name=p639 lab=A}
C {devices/lab_pin.sym} 3160 -1225 0 0 {name=p640 lab=LOWLVPWR}
C {devices/lab_pin.sym} 3340 -1245 0 1 {name=p641 lab=X}
C {devices/lab_pin.sym} 3160 -1175 0 0 {name=p642 lab=A}
C {devices/lab_pin.sym} 3160 -1155 0 0 {name=p643 lab=VPWRIN}
C {devices/lab_pin.sym} 3340 -1175 0 1 {name=p644 lab=X}
C {sky130_stdcells/macro_sparecell.sym} 3250 -1490 0 0 {name=x155 VGND=VGND VNB=VNB VPB=VPB VPWR=VPWR prefix=sky130_fd_sc_hd__ }
C {sky130_stdcells/clkinvlp_2.sym} 1300 -1850 0 0 {name=x156 VGND=VGND VNB=VNB VPB=VPB VPWR=VPWR prefix=sky130_fd_sc_hd__ }
C {sky130_stdcells/lpflow_lsbuf_lh_isowell_tap_4.sym} 3250 -1550 0 0 {name=x157 VGND=VGND VPB=VPB VPWR=VPWR prefix=sky130_fd_sc_hd__ }
C {sky130_stdcells/diode_2.sym} 3530 -270 0 0 {name=x158 VGND=VGND VNB=VNB VPB=VPB VPWR=VPWR prefix=sky130_fd_sc_hd__ }
C {sky130_stdcells/lpflow_decapkapwr_3.sym} 3530 -310 0 0 {name=x159 VGND=VGND VNB=VNB VPB=VPB VPWR=VPWR prefix=sky130_fd_sc_hd__ }
C {sky130_stdcells/lpflow_isobufsrckapwr_16.sym} 3530 -380 0 0 {name=x160 VGND=VGND VNB=VNB VPB=VPB VPWR=VPWR prefix=sky130_fd_sc_hd__ }
C {sky130_stdcells/decap_3.sym} 3530 -470 0 0 {name=x161 VGND=VGND VNB=VNB VPB=VPB VPWR=VPWR prefix=sky130_fd_sc_hd__ }
C {sky130_stdcells/bufbuf_8.sym} 1300 -1710 0 0 {name=x162 VGND=VGND VNB=VNB VPB=VPB VPWR=VPWR prefix=sky130_fd_sc_hd__ }
C {sky130_stdcells/bufinv_8.sym} 1300 -1780 0 0 {name=x163 VGND=VGND VNB=VNB VPB=VPB VPWR=VPWR prefix=sky130_fd_sc_hd__ }
C {sky130_stdcells/probe_p_8.sym} 3530 -520 0 0 {name=x164 VGND=VGND VNB=VNB VPB=VPB VPWR=VPWR prefix=sky130_fd_sc_hd__ }
C {sky130_stdcells/probec_p_8.sym} 3530 -580 0 0 {name=x165 VGND=VGND VNB=VNB VPB=VPB VPWR=VPWR prefix=sky130_fd_sc_hd__ }
C {devices/lab_pin.sym} 3340 -1490 0 1 {name=p645 lab=LO}
C {devices/lab_pin.sym} 1260 -1850 0 0 {name=p646 lab=A}
C {devices/lab_pin.sym} 1340 -1850 0 1 {name=p647 lab=Y}
C {devices/lab_pin.sym} 3160 -1560 0 0 {name=p648 lab=A}
C {devices/lab_pin.sym} 3160 -1540 0 0 {name=p649 lab=LOWLVPWR}
C {devices/lab_pin.sym} 3340 -1560 0 1 {name=p650 lab=X}
C {devices/lab_pin.sym} 3440 -270 0 0 {name=p651 lab=DIODE}
C {devices/lab_pin.sym} 3440 -310 0 0 {name=p652 lab=KAPWR}
C {devices/lab_pin.sym} 3440 -400 0 0 {name=p653 lab=A}
C {devices/lab_pin.sym} 3440 -380 0 0 {name=p654 lab=SLEEP}
C {devices/lab_pin.sym} 3440 -360 0 0 {name=p655 lab=KAPWR}
C {devices/lab_pin.sym} 3620 -400 0 1 {name=p656 lab=X}
C {devices/lab_pin.sym} 1260 -1710 0 0 {name=p657 lab=A}
C {devices/lab_pin.sym} 1340 -1710 0 1 {name=p658 lab=X}
C {devices/lab_pin.sym} 1260 -1780 0 0 {name=p659 lab=A}
C {devices/lab_pin.sym} 1340 -1780 0 1 {name=p660 lab=Y}
C {devices/lab_pin.sym} 3440 -520 0 0 {name=p661 lab=A}
C {devices/lab_pin.sym} 3620 -520 0 1 {name=p662 lab=X}
C {devices/lab_pin.sym} 3440 -580 0 0 {name=p663 lab=A}
C {devices/lab_pin.sym} 3620 -580 0 1 {name=p664 lab=X}
